VERSION 5.7 ;
  NOWIREEXTENSIONATPIN ON ;
  DIVIDERCHAR "/" ;
  BUSBITCHARS "[]" ;
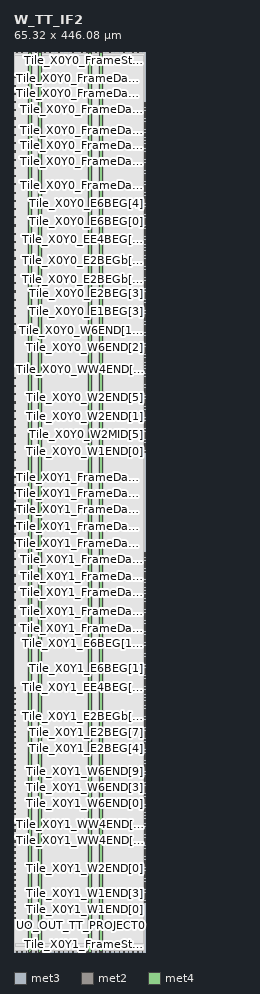
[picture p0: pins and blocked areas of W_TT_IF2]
MACRO W_TT_IF2
  CLASS BLOCK ;
  FOREIGN W_TT_IF2 ;
  ORIGIN 0.000 0.000 ;
  SIZE 65.320 BY 446.080 ;
  PIN CLK_TT_PROJECT
    DIRECTION OUTPUT ;
    USE SIGNAL ;
    ANTENNADIFFAREA 0.702900 ;
    PORT
      LAYER met3 ;
        RECT 0.000 127.880 0.600 128.480 ;
    END
  END CLK_TT_PROJECT
  PIN ENA_TT_PROJECT
    DIRECTION OUTPUT ;
    USE SIGNAL ;
    ANTENNADIFFAREA 0.702900 ;
    PORT
      LAYER met3 ;
        RECT 0.000 125.160 0.600 125.760 ;
    END
  END ENA_TT_PROJECT
  PIN RST_N_TT_PROJECT
    DIRECTION OUTPUT ;
    USE SIGNAL ;
    ANTENNADIFFAREA 0.702900 ;
    PORT
      LAYER met3 ;
        RECT 0.000 130.600 0.600 131.200 ;
    END
  END RST_N_TT_PROJECT
  PIN Tile_X0Y0_E1BEG[0]
    DIRECTION OUTPUT ;
    USE SIGNAL ;
    ANTENNADIFFAREA 0.702900 ;
    PORT
      LAYER met3 ;
        RECT 64.720 312.840 65.320 313.440 ;
    END
  END Tile_X0Y0_E1BEG[0]
  PIN Tile_X0Y0_E1BEG[1]
    DIRECTION OUTPUT ;
    USE SIGNAL ;
    ANTENNADIFFAREA 0.702900 ;
    PORT
      LAYER met3 ;
        RECT 64.720 314.200 65.320 314.800 ;
    END
  END Tile_X0Y0_E1BEG[1]
  PIN Tile_X0Y0_E1BEG[2]
    DIRECTION OUTPUT ;
    USE SIGNAL ;
    ANTENNADIFFAREA 0.702900 ;
    PORT
      LAYER met3 ;
        RECT 64.720 315.560 65.320 316.160 ;
    END
  END Tile_X0Y0_E1BEG[2]
  PIN Tile_X0Y0_E1BEG[3]
    DIRECTION OUTPUT ;
    USE SIGNAL ;
    ANTENNADIFFAREA 0.702900 ;
    PORT
      LAYER met3 ;
        RECT 64.720 316.920 65.320 317.520 ;
    END
  END Tile_X0Y0_E1BEG[3]
  PIN Tile_X0Y0_E2BEG[0]
    DIRECTION OUTPUT ;
    USE SIGNAL ;
    ANTENNADIFFAREA 0.702900 ;
    PORT
      LAYER met3 ;
        RECT 64.720 318.280 65.320 318.880 ;
    END
  END Tile_X0Y0_E2BEG[0]
  PIN Tile_X0Y0_E2BEG[1]
    DIRECTION OUTPUT ;
    USE SIGNAL ;
    ANTENNADIFFAREA 0.702900 ;
    PORT
      LAYER met3 ;
        RECT 64.720 319.640 65.320 320.240 ;
    END
  END Tile_X0Y0_E2BEG[1]
  PIN Tile_X0Y0_E2BEG[2]
    DIRECTION OUTPUT ;
    USE SIGNAL ;
    ANTENNADIFFAREA 0.702900 ;
    PORT
      LAYER met3 ;
        RECT 64.720 321.000 65.320 321.600 ;
    END
  END Tile_X0Y0_E2BEG[2]
  PIN Tile_X0Y0_E2BEG[3]
    DIRECTION OUTPUT ;
    USE SIGNAL ;
    ANTENNADIFFAREA 0.702900 ;
    PORT
      LAYER met3 ;
        RECT 64.720 322.360 65.320 322.960 ;
    END
  END Tile_X0Y0_E2BEG[3]
  PIN Tile_X0Y0_E2BEG[4]
    DIRECTION OUTPUT ;
    USE SIGNAL ;
    ANTENNADIFFAREA 0.702900 ;
    PORT
      LAYER met3 ;
        RECT 64.720 323.720 65.320 324.320 ;
    END
  END Tile_X0Y0_E2BEG[4]
  PIN Tile_X0Y0_E2BEG[5]
    DIRECTION OUTPUT ;
    USE SIGNAL ;
    ANTENNADIFFAREA 0.702900 ;
    PORT
      LAYER met3 ;
        RECT 64.720 325.080 65.320 325.680 ;
    END
  END Tile_X0Y0_E2BEG[5]
  PIN Tile_X0Y0_E2BEG[6]
    DIRECTION OUTPUT ;
    USE SIGNAL ;
    ANTENNADIFFAREA 0.702900 ;
    PORT
      LAYER met3 ;
        RECT 64.720 326.440 65.320 327.040 ;
    END
  END Tile_X0Y0_E2BEG[6]
  PIN Tile_X0Y0_E2BEG[7]
    DIRECTION OUTPUT ;
    USE SIGNAL ;
    ANTENNADIFFAREA 0.702900 ;
    PORT
      LAYER met3 ;
        RECT 64.720 327.800 65.320 328.400 ;
    END
  END Tile_X0Y0_E2BEG[7]
  PIN Tile_X0Y0_E2BEGb[0]
    DIRECTION OUTPUT ;
    USE SIGNAL ;
    ANTENNADIFFAREA 0.702900 ;
    PORT
      LAYER met3 ;
        RECT 64.720 329.160 65.320 329.760 ;
    END
  END Tile_X0Y0_E2BEGb[0]
  PIN Tile_X0Y0_E2BEGb[1]
    DIRECTION OUTPUT ;
    USE SIGNAL ;
    ANTENNADIFFAREA 0.702900 ;
    PORT
      LAYER met3 ;
        RECT 64.720 330.520 65.320 331.120 ;
    END
  END Tile_X0Y0_E2BEGb[1]
  PIN Tile_X0Y0_E2BEGb[2]
    DIRECTION OUTPUT ;
    USE SIGNAL ;
    ANTENNADIFFAREA 0.702900 ;
    PORT
      LAYER met3 ;
        RECT 64.720 331.880 65.320 332.480 ;
    END
  END Tile_X0Y0_E2BEGb[2]
  PIN Tile_X0Y0_E2BEGb[3]
    DIRECTION OUTPUT ;
    USE SIGNAL ;
    ANTENNADIFFAREA 0.702900 ;
    PORT
      LAYER met3 ;
        RECT 64.720 333.240 65.320 333.840 ;
    END
  END Tile_X0Y0_E2BEGb[3]
  PIN Tile_X0Y0_E2BEGb[4]
    DIRECTION OUTPUT ;
    USE SIGNAL ;
    ANTENNADIFFAREA 0.702900 ;
    PORT
      LAYER met3 ;
        RECT 64.720 334.600 65.320 335.200 ;
    END
  END Tile_X0Y0_E2BEGb[4]
  PIN Tile_X0Y0_E2BEGb[5]
    DIRECTION OUTPUT ;
    USE SIGNAL ;
    ANTENNADIFFAREA 0.702900 ;
    PORT
      LAYER met3 ;
        RECT 64.720 335.960 65.320 336.560 ;
    END
  END Tile_X0Y0_E2BEGb[5]
  PIN Tile_X0Y0_E2BEGb[6]
    DIRECTION OUTPUT ;
    USE SIGNAL ;
    ANTENNADIFFAREA 0.702900 ;
    PORT
      LAYER met3 ;
        RECT 64.720 337.320 65.320 337.920 ;
    END
  END Tile_X0Y0_E2BEGb[6]
  PIN Tile_X0Y0_E2BEGb[7]
    DIRECTION OUTPUT ;
    USE SIGNAL ;
    ANTENNADIFFAREA 0.702900 ;
    PORT
      LAYER met3 ;
        RECT 64.720 338.680 65.320 339.280 ;
    END
  END Tile_X0Y0_E2BEGb[7]
  PIN Tile_X0Y0_E6BEG[0]
    DIRECTION OUTPUT ;
    USE SIGNAL ;
    ANTENNADIFFAREA 0.702900 ;
    PORT
      LAYER met3 ;
        RECT 64.720 361.800 65.320 362.400 ;
    END
  END Tile_X0Y0_E6BEG[0]
  PIN Tile_X0Y0_E6BEG[10]
    DIRECTION OUTPUT ;
    USE SIGNAL ;
    ANTENNADIFFAREA 0.702900 ;
    PORT
      LAYER met3 ;
        RECT 64.720 375.400 65.320 376.000 ;
    END
  END Tile_X0Y0_E6BEG[10]
  PIN Tile_X0Y0_E6BEG[11]
    DIRECTION OUTPUT ;
    USE SIGNAL ;
    ANTENNADIFFAREA 0.702900 ;
    PORT
      LAYER met3 ;
        RECT 64.720 376.760 65.320 377.360 ;
    END
  END Tile_X0Y0_E6BEG[11]
  PIN Tile_X0Y0_E6BEG[1]
    DIRECTION OUTPUT ;
    USE SIGNAL ;
    ANTENNADIFFAREA 0.702900 ;
    PORT
      LAYER met3 ;
        RECT 64.720 363.160 65.320 363.760 ;
    END
  END Tile_X0Y0_E6BEG[1]
  PIN Tile_X0Y0_E6BEG[2]
    DIRECTION OUTPUT ;
    USE SIGNAL ;
    ANTENNADIFFAREA 0.702900 ;
    PORT
      LAYER met3 ;
        RECT 64.720 364.520 65.320 365.120 ;
    END
  END Tile_X0Y0_E6BEG[2]
  PIN Tile_X0Y0_E6BEG[3]
    DIRECTION OUTPUT ;
    USE SIGNAL ;
    ANTENNADIFFAREA 0.702900 ;
    PORT
      LAYER met3 ;
        RECT 64.720 365.880 65.320 366.480 ;
    END
  END Tile_X0Y0_E6BEG[3]
  PIN Tile_X0Y0_E6BEG[4]
    DIRECTION OUTPUT ;
    USE SIGNAL ;
    ANTENNADIFFAREA 0.702900 ;
    PORT
      LAYER met3 ;
        RECT 64.720 367.240 65.320 367.840 ;
    END
  END Tile_X0Y0_E6BEG[4]
  PIN Tile_X0Y0_E6BEG[5]
    DIRECTION OUTPUT ;
    USE SIGNAL ;
    ANTENNADIFFAREA 0.702900 ;
    PORT
      LAYER met3 ;
        RECT 64.720 368.600 65.320 369.200 ;
    END
  END Tile_X0Y0_E6BEG[5]
  PIN Tile_X0Y0_E6BEG[6]
    DIRECTION OUTPUT ;
    USE SIGNAL ;
    ANTENNADIFFAREA 0.702900 ;
    PORT
      LAYER met3 ;
        RECT 64.720 369.960 65.320 370.560 ;
    END
  END Tile_X0Y0_E6BEG[6]
  PIN Tile_X0Y0_E6BEG[7]
    DIRECTION OUTPUT ;
    USE SIGNAL ;
    ANTENNADIFFAREA 0.702900 ;
    PORT
      LAYER met3 ;
        RECT 64.720 371.320 65.320 371.920 ;
    END
  END Tile_X0Y0_E6BEG[7]
  PIN Tile_X0Y0_E6BEG[8]
    DIRECTION OUTPUT ;
    USE SIGNAL ;
    ANTENNADIFFAREA 0.702900 ;
    PORT
      LAYER met3 ;
        RECT 64.720 372.680 65.320 373.280 ;
    END
  END Tile_X0Y0_E6BEG[8]
  PIN Tile_X0Y0_E6BEG[9]
    DIRECTION OUTPUT ;
    USE SIGNAL ;
    ANTENNADIFFAREA 0.702900 ;
    PORT
      LAYER met3 ;
        RECT 64.720 374.040 65.320 374.640 ;
    END
  END Tile_X0Y0_E6BEG[9]
  PIN Tile_X0Y0_EE4BEG[0]
    DIRECTION OUTPUT ;
    USE SIGNAL ;
    ANTENNADIFFAREA 0.702900 ;
    PORT
      LAYER met3 ;
        RECT 64.720 340.040 65.320 340.640 ;
    END
  END Tile_X0Y0_EE4BEG[0]
  PIN Tile_X0Y0_EE4BEG[10]
    DIRECTION OUTPUT ;
    USE SIGNAL ;
    ANTENNADIFFAREA 0.702900 ;
    PORT
      LAYER met3 ;
        RECT 64.720 353.640 65.320 354.240 ;
    END
  END Tile_X0Y0_EE4BEG[10]
  PIN Tile_X0Y0_EE4BEG[11]
    DIRECTION OUTPUT ;
    USE SIGNAL ;
    ANTENNADIFFAREA 0.702900 ;
    PORT
      LAYER met3 ;
        RECT 64.720 355.000 65.320 355.600 ;
    END
  END Tile_X0Y0_EE4BEG[11]
  PIN Tile_X0Y0_EE4BEG[12]
    DIRECTION OUTPUT ;
    USE SIGNAL ;
    ANTENNADIFFAREA 0.702900 ;
    PORT
      LAYER met3 ;
        RECT 64.720 356.360 65.320 356.960 ;
    END
  END Tile_X0Y0_EE4BEG[12]
  PIN Tile_X0Y0_EE4BEG[13]
    DIRECTION OUTPUT ;
    USE SIGNAL ;
    ANTENNADIFFAREA 0.702900 ;
    PORT
      LAYER met3 ;
        RECT 64.720 357.720 65.320 358.320 ;
    END
  END Tile_X0Y0_EE4BEG[13]
  PIN Tile_X0Y0_EE4BEG[14]
    DIRECTION OUTPUT ;
    USE SIGNAL ;
    ANTENNADIFFAREA 0.702900 ;
    PORT
      LAYER met3 ;
        RECT 64.720 359.080 65.320 359.680 ;
    END
  END Tile_X0Y0_EE4BEG[14]
  PIN Tile_X0Y0_EE4BEG[15]
    DIRECTION OUTPUT ;
    USE SIGNAL ;
    ANTENNADIFFAREA 0.702900 ;
    PORT
      LAYER met3 ;
        RECT 64.720 360.440 65.320 361.040 ;
    END
  END Tile_X0Y0_EE4BEG[15]
  PIN Tile_X0Y0_EE4BEG[1]
    DIRECTION OUTPUT ;
    USE SIGNAL ;
    ANTENNADIFFAREA 0.702900 ;
    PORT
      LAYER met3 ;
        RECT 64.720 341.400 65.320 342.000 ;
    END
  END Tile_X0Y0_EE4BEG[1]
  PIN Tile_X0Y0_EE4BEG[2]
    DIRECTION OUTPUT ;
    USE SIGNAL ;
    ANTENNADIFFAREA 0.702900 ;
    PORT
      LAYER met3 ;
        RECT 64.720 342.760 65.320 343.360 ;
    END
  END Tile_X0Y0_EE4BEG[2]
  PIN Tile_X0Y0_EE4BEG[3]
    DIRECTION OUTPUT ;
    USE SIGNAL ;
    ANTENNADIFFAREA 0.702900 ;
    PORT
      LAYER met3 ;
        RECT 64.720 344.120 65.320 344.720 ;
    END
  END Tile_X0Y0_EE4BEG[3]
  PIN Tile_X0Y0_EE4BEG[4]
    DIRECTION OUTPUT ;
    USE SIGNAL ;
    ANTENNADIFFAREA 0.702900 ;
    PORT
      LAYER met3 ;
        RECT 64.720 345.480 65.320 346.080 ;
    END
  END Tile_X0Y0_EE4BEG[4]
  PIN Tile_X0Y0_EE4BEG[5]
    DIRECTION OUTPUT ;
    USE SIGNAL ;
    ANTENNADIFFAREA 0.702900 ;
    PORT
      LAYER met3 ;
        RECT 64.720 346.840 65.320 347.440 ;
    END
  END Tile_X0Y0_EE4BEG[5]
  PIN Tile_X0Y0_EE4BEG[6]
    DIRECTION OUTPUT ;
    USE SIGNAL ;
    ANTENNADIFFAREA 0.702900 ;
    PORT
      LAYER met3 ;
        RECT 64.720 348.200 65.320 348.800 ;
    END
  END Tile_X0Y0_EE4BEG[6]
  PIN Tile_X0Y0_EE4BEG[7]
    DIRECTION OUTPUT ;
    USE SIGNAL ;
    ANTENNADIFFAREA 0.702900 ;
    PORT
      LAYER met3 ;
        RECT 64.720 349.560 65.320 350.160 ;
    END
  END Tile_X0Y0_EE4BEG[7]
  PIN Tile_X0Y0_EE4BEG[8]
    DIRECTION OUTPUT ;
    USE SIGNAL ;
    ANTENNADIFFAREA 0.702900 ;
    PORT
      LAYER met3 ;
        RECT 64.720 350.920 65.320 351.520 ;
    END
  END Tile_X0Y0_EE4BEG[8]
  PIN Tile_X0Y0_EE4BEG[9]
    DIRECTION OUTPUT ;
    USE SIGNAL ;
    ANTENNADIFFAREA 0.702900 ;
    PORT
      LAYER met3 ;
        RECT 64.720 352.280 65.320 352.880 ;
    END
  END Tile_X0Y0_EE4BEG[9]
  PIN Tile_X0Y0_FrameData[0]
    DIRECTION INPUT ;
    USE SIGNAL ;
    ANTENNAGATEAREA 1.505400 ;
    ANTENNADIFFAREA 0.869400 ;
    PORT
      LAYER met3 ;
        RECT 0.000 306.720 0.600 307.320 ;
    END
  END Tile_X0Y0_FrameData[0]
  PIN Tile_X0Y0_FrameData[10]
    DIRECTION INPUT ;
    USE SIGNAL ;
    ANTENNAGATEAREA 0.795000 ;
    PORT
      LAYER met3 ;
        RECT 0.000 347.520 0.600 348.120 ;
    END
  END Tile_X0Y0_FrameData[10]
  PIN Tile_X0Y0_FrameData[11]
    DIRECTION INPUT ;
    USE SIGNAL ;
    ANTENNAGATEAREA 0.795000 ;
    PORT
      LAYER met3 ;
        RECT 0.000 351.600 0.600 352.200 ;
    END
  END Tile_X0Y0_FrameData[11]
  PIN Tile_X0Y0_FrameData[12]
    DIRECTION INPUT ;
    USE SIGNAL ;
    ANTENNAGATEAREA 0.795000 ;
    PORT
      LAYER met3 ;
        RECT 0.000 355.680 0.600 356.280 ;
    END
  END Tile_X0Y0_FrameData[12]
  PIN Tile_X0Y0_FrameData[13]
    DIRECTION INPUT ;
    USE SIGNAL ;
    ANTENNAGATEAREA 0.795000 ;
    PORT
      LAYER met3 ;
        RECT 0.000 359.760 0.600 360.360 ;
    END
  END Tile_X0Y0_FrameData[13]
  PIN Tile_X0Y0_FrameData[14]
    DIRECTION INPUT ;
    USE SIGNAL ;
    ANTENNAGATEAREA 0.795000 ;
    PORT
      LAYER met3 ;
        RECT 0.000 363.840 0.600 364.440 ;
    END
  END Tile_X0Y0_FrameData[14]
  PIN Tile_X0Y0_FrameData[15]
    DIRECTION INPUT ;
    USE SIGNAL ;
    ANTENNAGATEAREA 0.795000 ;
    PORT
      LAYER met3 ;
        RECT 0.000 367.920 0.600 368.520 ;
    END
  END Tile_X0Y0_FrameData[15]
  PIN Tile_X0Y0_FrameData[16]
    DIRECTION INPUT ;
    USE SIGNAL ;
    ANTENNAGATEAREA 0.795000 ;
    PORT
      LAYER met3 ;
        RECT 0.000 372.000 0.600 372.600 ;
    END
  END Tile_X0Y0_FrameData[16]
  PIN Tile_X0Y0_FrameData[17]
    DIRECTION INPUT ;
    USE SIGNAL ;
    ANTENNAGATEAREA 0.795000 ;
    PORT
      LAYER met3 ;
        RECT 0.000 376.080 0.600 376.680 ;
    END
  END Tile_X0Y0_FrameData[17]
  PIN Tile_X0Y0_FrameData[18]
    DIRECTION INPUT ;
    USE SIGNAL ;
    ANTENNAGATEAREA 0.795000 ;
    PORT
      LAYER met3 ;
        RECT 0.000 380.160 0.600 380.760 ;
    END
  END Tile_X0Y0_FrameData[18]
  PIN Tile_X0Y0_FrameData[19]
    DIRECTION INPUT ;
    USE SIGNAL ;
    ANTENNAGATEAREA 0.795000 ;
    PORT
      LAYER met3 ;
        RECT 0.000 384.240 0.600 384.840 ;
    END
  END Tile_X0Y0_FrameData[19]
  PIN Tile_X0Y0_FrameData[1]
    DIRECTION INPUT ;
    USE SIGNAL ;
    ANTENNAGATEAREA 1.070700 ;
    ANTENNADIFFAREA 0.434700 ;
    PORT
      LAYER met3 ;
        RECT 0.000 310.800 0.600 311.400 ;
    END
  END Tile_X0Y0_FrameData[1]
  PIN Tile_X0Y0_FrameData[20]
    DIRECTION INPUT ;
    USE SIGNAL ;
    ANTENNAGATEAREA 0.795000 ;
    PORT
      LAYER met3 ;
        RECT 0.000 388.320 0.600 388.920 ;
    END
  END Tile_X0Y0_FrameData[20]
  PIN Tile_X0Y0_FrameData[21]
    DIRECTION INPUT ;
    USE SIGNAL ;
    ANTENNAGATEAREA 0.795000 ;
    PORT
      LAYER met3 ;
        RECT 0.000 392.400 0.600 393.000 ;
    END
  END Tile_X0Y0_FrameData[21]
  PIN Tile_X0Y0_FrameData[22]
    DIRECTION INPUT ;
    USE SIGNAL ;
    ANTENNAGATEAREA 0.795000 ;
    PORT
      LAYER met3 ;
        RECT 0.000 396.480 0.600 397.080 ;
    END
  END Tile_X0Y0_FrameData[22]
  PIN Tile_X0Y0_FrameData[23]
    DIRECTION INPUT ;
    USE SIGNAL ;
    ANTENNAGATEAREA 0.795000 ;
    PORT
      LAYER met3 ;
        RECT 0.000 400.560 0.600 401.160 ;
    END
  END Tile_X0Y0_FrameData[23]
  PIN Tile_X0Y0_FrameData[24]
    DIRECTION INPUT ;
    USE SIGNAL ;
    ANTENNAGATEAREA 0.795000 ;
    PORT
      LAYER met3 ;
        RECT 0.000 404.640 0.600 405.240 ;
    END
  END Tile_X0Y0_FrameData[24]
  PIN Tile_X0Y0_FrameData[25]
    DIRECTION INPUT ;
    USE SIGNAL ;
    ANTENNAGATEAREA 1.229700 ;
    ANTENNADIFFAREA 0.434700 ;
    PORT
      LAYER met3 ;
        RECT 0.000 408.720 0.600 409.320 ;
    END
  END Tile_X0Y0_FrameData[25]
  PIN Tile_X0Y0_FrameData[26]
    DIRECTION INPUT ;
    USE SIGNAL ;
    ANTENNAGATEAREA 1.229700 ;
    ANTENNADIFFAREA 0.434700 ;
    PORT
      LAYER met3 ;
        RECT 0.000 412.800 0.600 413.400 ;
    END
  END Tile_X0Y0_FrameData[26]
  PIN Tile_X0Y0_FrameData[27]
    DIRECTION INPUT ;
    USE SIGNAL ;
    ANTENNAGATEAREA 0.795000 ;
    PORT
      LAYER met3 ;
        RECT 0.000 416.880 0.600 417.480 ;
    END
  END Tile_X0Y0_FrameData[27]
  PIN Tile_X0Y0_FrameData[28]
    DIRECTION INPUT ;
    USE SIGNAL ;
    ANTENNAGATEAREA 1.229700 ;
    ANTENNADIFFAREA 0.434700 ;
    PORT
      LAYER met3 ;
        RECT 0.000 420.960 0.600 421.560 ;
    END
  END Tile_X0Y0_FrameData[28]
  PIN Tile_X0Y0_FrameData[29]
    DIRECTION INPUT ;
    USE SIGNAL ;
    ANTENNAGATEAREA 1.229700 ;
    ANTENNADIFFAREA 0.434700 ;
    PORT
      LAYER met3 ;
        RECT 0.000 425.040 0.600 425.640 ;
    END
  END Tile_X0Y0_FrameData[29]
  PIN Tile_X0Y0_FrameData[2]
    DIRECTION INPUT ;
    USE SIGNAL ;
    ANTENNAGATEAREA 0.636000 ;
    PORT
      LAYER met3 ;
        RECT 0.000 314.880 0.600 315.480 ;
    END
  END Tile_X0Y0_FrameData[2]
  PIN Tile_X0Y0_FrameData[30]
    DIRECTION INPUT ;
    USE SIGNAL ;
    ANTENNAGATEAREA 0.795000 ;
    PORT
      LAYER met3 ;
        RECT 0.000 429.120 0.600 429.720 ;
    END
  END Tile_X0Y0_FrameData[30]
  PIN Tile_X0Y0_FrameData[31]
    DIRECTION INPUT ;
    USE SIGNAL ;
    ANTENNAGATEAREA 0.795000 ;
    PORT
      LAYER met3 ;
        RECT 0.000 433.200 0.600 433.800 ;
    END
  END Tile_X0Y0_FrameData[31]
  PIN Tile_X0Y0_FrameData[3]
    DIRECTION INPUT ;
    USE SIGNAL ;
    ANTENNAGATEAREA 0.636000 ;
    PORT
      LAYER met3 ;
        RECT 0.000 318.960 0.600 319.560 ;
    END
  END Tile_X0Y0_FrameData[3]
  PIN Tile_X0Y0_FrameData[4]
    DIRECTION INPUT ;
    USE SIGNAL ;
    ANTENNAGATEAREA 0.795000 ;
    PORT
      LAYER met3 ;
        RECT 0.000 323.040 0.600 323.640 ;
    END
  END Tile_X0Y0_FrameData[4]
  PIN Tile_X0Y0_FrameData[5]
    DIRECTION INPUT ;
    USE SIGNAL ;
    ANTENNAGATEAREA 0.795000 ;
    PORT
      LAYER met3 ;
        RECT 0.000 327.120 0.600 327.720 ;
    END
  END Tile_X0Y0_FrameData[5]
  PIN Tile_X0Y0_FrameData[6]
    DIRECTION INPUT ;
    USE SIGNAL ;
    ANTENNAGATEAREA 0.795000 ;
    PORT
      LAYER met3 ;
        RECT 0.000 331.200 0.600 331.800 ;
    END
  END Tile_X0Y0_FrameData[6]
  PIN Tile_X0Y0_FrameData[7]
    DIRECTION INPUT ;
    USE SIGNAL ;
    ANTENNAGATEAREA 0.795000 ;
    PORT
      LAYER met3 ;
        RECT 0.000 335.280 0.600 335.880 ;
    END
  END Tile_X0Y0_FrameData[7]
  PIN Tile_X0Y0_FrameData[8]
    DIRECTION INPUT ;
    USE SIGNAL ;
    ANTENNAGATEAREA 0.795000 ;
    PORT
      LAYER met3 ;
        RECT 0.000 339.360 0.600 339.960 ;
    END
  END Tile_X0Y0_FrameData[8]
  PIN Tile_X0Y0_FrameData[9]
    DIRECTION INPUT ;
    USE SIGNAL ;
    ANTENNAGATEAREA 1.229700 ;
    ANTENNADIFFAREA 0.434700 ;
    PORT
      LAYER met3 ;
        RECT 0.000 343.440 0.600 344.040 ;
    END
  END Tile_X0Y0_FrameData[9]
  PIN Tile_X0Y0_FrameData_O[0]
    DIRECTION OUTPUT ;
    USE SIGNAL ;
    ANTENNADIFFAREA 0.702900 ;
    PORT
      LAYER met3 ;
        RECT 64.720 378.120 65.320 378.720 ;
    END
  END Tile_X0Y0_FrameData_O[0]
  PIN Tile_X0Y0_FrameData_O[10]
    DIRECTION OUTPUT ;
    USE SIGNAL ;
    ANTENNADIFFAREA 0.702900 ;
    PORT
      LAYER met3 ;
        RECT 64.720 391.720 65.320 392.320 ;
    END
  END Tile_X0Y0_FrameData_O[10]
  PIN Tile_X0Y0_FrameData_O[11]
    DIRECTION OUTPUT ;
    USE SIGNAL ;
    ANTENNADIFFAREA 0.702900 ;
    PORT
      LAYER met3 ;
        RECT 64.720 393.080 65.320 393.680 ;
    END
  END Tile_X0Y0_FrameData_O[11]
  PIN Tile_X0Y0_FrameData_O[12]
    DIRECTION OUTPUT ;
    USE SIGNAL ;
    ANTENNADIFFAREA 0.702900 ;
    PORT
      LAYER met3 ;
        RECT 64.720 394.440 65.320 395.040 ;
    END
  END Tile_X0Y0_FrameData_O[12]
  PIN Tile_X0Y0_FrameData_O[13]
    DIRECTION OUTPUT ;
    USE SIGNAL ;
    ANTENNADIFFAREA 0.702900 ;
    PORT
      LAYER met3 ;
        RECT 64.720 395.800 65.320 396.400 ;
    END
  END Tile_X0Y0_FrameData_O[13]
  PIN Tile_X0Y0_FrameData_O[14]
    DIRECTION OUTPUT ;
    USE SIGNAL ;
    ANTENNADIFFAREA 0.702900 ;
    PORT
      LAYER met3 ;
        RECT 64.720 397.160 65.320 397.760 ;
    END
  END Tile_X0Y0_FrameData_O[14]
  PIN Tile_X0Y0_FrameData_O[15]
    DIRECTION OUTPUT ;
    USE SIGNAL ;
    ANTENNADIFFAREA 0.702900 ;
    PORT
      LAYER met3 ;
        RECT 64.720 398.520 65.320 399.120 ;
    END
  END Tile_X0Y0_FrameData_O[15]
  PIN Tile_X0Y0_FrameData_O[16]
    DIRECTION OUTPUT ;
    USE SIGNAL ;
    ANTENNADIFFAREA 0.702900 ;
    PORT
      LAYER met3 ;
        RECT 64.720 399.880 65.320 400.480 ;
    END
  END Tile_X0Y0_FrameData_O[16]
  PIN Tile_X0Y0_FrameData_O[17]
    DIRECTION OUTPUT ;
    USE SIGNAL ;
    ANTENNADIFFAREA 0.702900 ;
    PORT
      LAYER met3 ;
        RECT 64.720 401.240 65.320 401.840 ;
    END
  END Tile_X0Y0_FrameData_O[17]
  PIN Tile_X0Y0_FrameData_O[18]
    DIRECTION OUTPUT ;
    USE SIGNAL ;
    ANTENNADIFFAREA 0.702900 ;
    PORT
      LAYER met3 ;
        RECT 64.720 402.600 65.320 403.200 ;
    END
  END Tile_X0Y0_FrameData_O[18]
  PIN Tile_X0Y0_FrameData_O[19]
    DIRECTION OUTPUT ;
    USE SIGNAL ;
    ANTENNADIFFAREA 0.702900 ;
    PORT
      LAYER met3 ;
        RECT 64.720 403.960 65.320 404.560 ;
    END
  END Tile_X0Y0_FrameData_O[19]
  PIN Tile_X0Y0_FrameData_O[1]
    DIRECTION OUTPUT ;
    USE SIGNAL ;
    ANTENNADIFFAREA 0.702900 ;
    PORT
      LAYER met3 ;
        RECT 64.720 379.480 65.320 380.080 ;
    END
  END Tile_X0Y0_FrameData_O[1]
  PIN Tile_X0Y0_FrameData_O[20]
    DIRECTION OUTPUT ;
    USE SIGNAL ;
    ANTENNADIFFAREA 0.702900 ;
    PORT
      LAYER met3 ;
        RECT 64.720 405.320 65.320 405.920 ;
    END
  END Tile_X0Y0_FrameData_O[20]
  PIN Tile_X0Y0_FrameData_O[21]
    DIRECTION OUTPUT ;
    USE SIGNAL ;
    ANTENNADIFFAREA 0.702900 ;
    PORT
      LAYER met3 ;
        RECT 64.720 406.680 65.320 407.280 ;
    END
  END Tile_X0Y0_FrameData_O[21]
  PIN Tile_X0Y0_FrameData_O[22]
    DIRECTION OUTPUT ;
    USE SIGNAL ;
    ANTENNADIFFAREA 0.702900 ;
    PORT
      LAYER met3 ;
        RECT 64.720 408.040 65.320 408.640 ;
    END
  END Tile_X0Y0_FrameData_O[22]
  PIN Tile_X0Y0_FrameData_O[23]
    DIRECTION OUTPUT ;
    USE SIGNAL ;
    ANTENNADIFFAREA 0.702900 ;
    PORT
      LAYER met3 ;
        RECT 64.720 409.400 65.320 410.000 ;
    END
  END Tile_X0Y0_FrameData_O[23]
  PIN Tile_X0Y0_FrameData_O[24]
    DIRECTION OUTPUT ;
    USE SIGNAL ;
    ANTENNADIFFAREA 0.702900 ;
    PORT
      LAYER met3 ;
        RECT 64.720 410.760 65.320 411.360 ;
    END
  END Tile_X0Y0_FrameData_O[24]
  PIN Tile_X0Y0_FrameData_O[25]
    DIRECTION OUTPUT ;
    USE SIGNAL ;
    ANTENNADIFFAREA 0.702900 ;
    PORT
      LAYER met3 ;
        RECT 64.720 412.120 65.320 412.720 ;
    END
  END Tile_X0Y0_FrameData_O[25]
  PIN Tile_X0Y0_FrameData_O[26]
    DIRECTION OUTPUT ;
    USE SIGNAL ;
    ANTENNADIFFAREA 0.702900 ;
    PORT
      LAYER met3 ;
        RECT 64.720 413.480 65.320 414.080 ;
    END
  END Tile_X0Y0_FrameData_O[26]
  PIN Tile_X0Y0_FrameData_O[27]
    DIRECTION OUTPUT ;
    USE SIGNAL ;
    ANTENNADIFFAREA 0.702900 ;
    PORT
      LAYER met3 ;
        RECT 64.720 414.840 65.320 415.440 ;
    END
  END Tile_X0Y0_FrameData_O[27]
  PIN Tile_X0Y0_FrameData_O[28]
    DIRECTION OUTPUT ;
    USE SIGNAL ;
    ANTENNADIFFAREA 0.702900 ;
    PORT
      LAYER met3 ;
        RECT 64.720 416.200 65.320 416.800 ;
    END
  END Tile_X0Y0_FrameData_O[28]
  PIN Tile_X0Y0_FrameData_O[29]
    DIRECTION OUTPUT ;
    USE SIGNAL ;
    ANTENNADIFFAREA 0.702900 ;
    PORT
      LAYER met3 ;
        RECT 64.720 417.560 65.320 418.160 ;
    END
  END Tile_X0Y0_FrameData_O[29]
  PIN Tile_X0Y0_FrameData_O[2]
    DIRECTION OUTPUT ;
    USE SIGNAL ;
    ANTENNADIFFAREA 0.702900 ;
    PORT
      LAYER met3 ;
        RECT 64.720 380.840 65.320 381.440 ;
    END
  END Tile_X0Y0_FrameData_O[2]
  PIN Tile_X0Y0_FrameData_O[30]
    DIRECTION OUTPUT ;
    USE SIGNAL ;
    ANTENNADIFFAREA 0.702900 ;
    PORT
      LAYER met3 ;
        RECT 64.720 418.920 65.320 419.520 ;
    END
  END Tile_X0Y0_FrameData_O[30]
  PIN Tile_X0Y0_FrameData_O[31]
    DIRECTION OUTPUT ;
    USE SIGNAL ;
    ANTENNADIFFAREA 0.702900 ;
    PORT
      LAYER met3 ;
        RECT 64.720 420.280 65.320 420.880 ;
    END
  END Tile_X0Y0_FrameData_O[31]
  PIN Tile_X0Y0_FrameData_O[3]
    DIRECTION OUTPUT ;
    USE SIGNAL ;
    ANTENNADIFFAREA 0.702900 ;
    PORT
      LAYER met3 ;
        RECT 64.720 382.200 65.320 382.800 ;
    END
  END Tile_X0Y0_FrameData_O[3]
  PIN Tile_X0Y0_FrameData_O[4]
    DIRECTION OUTPUT ;
    USE SIGNAL ;
    ANTENNADIFFAREA 0.702900 ;
    PORT
      LAYER met3 ;
        RECT 64.720 383.560 65.320 384.160 ;
    END
  END Tile_X0Y0_FrameData_O[4]
  PIN Tile_X0Y0_FrameData_O[5]
    DIRECTION OUTPUT ;
    USE SIGNAL ;
    ANTENNADIFFAREA 0.702900 ;
    PORT
      LAYER met3 ;
        RECT 64.720 384.920 65.320 385.520 ;
    END
  END Tile_X0Y0_FrameData_O[5]
  PIN Tile_X0Y0_FrameData_O[6]
    DIRECTION OUTPUT ;
    USE SIGNAL ;
    ANTENNADIFFAREA 0.702900 ;
    PORT
      LAYER met3 ;
        RECT 64.720 386.280 65.320 386.880 ;
    END
  END Tile_X0Y0_FrameData_O[6]
  PIN Tile_X0Y0_FrameData_O[7]
    DIRECTION OUTPUT ;
    USE SIGNAL ;
    ANTENNADIFFAREA 0.702900 ;
    PORT
      LAYER met3 ;
        RECT 64.720 387.640 65.320 388.240 ;
    END
  END Tile_X0Y0_FrameData_O[7]
  PIN Tile_X0Y0_FrameData_O[8]
    DIRECTION OUTPUT ;
    USE SIGNAL ;
    ANTENNADIFFAREA 0.702900 ;
    PORT
      LAYER met3 ;
        RECT 64.720 389.000 65.320 389.600 ;
    END
  END Tile_X0Y0_FrameData_O[8]
  PIN Tile_X0Y0_FrameData_O[9]
    DIRECTION OUTPUT ;
    USE SIGNAL ;
    ANTENNADIFFAREA 0.702900 ;
    PORT
      LAYER met3 ;
        RECT 64.720 390.360 65.320 390.960 ;
    END
  END Tile_X0Y0_FrameData_O[9]
  PIN Tile_X0Y0_FrameStrobe_O[0]
    DIRECTION OUTPUT ;
    USE SIGNAL ;
    ANTENNADIFFAREA 0.702900 ;
    PORT
      LAYER met2 ;
        RECT 19.870 445.800 20.150 446.080 ;
    END
  END Tile_X0Y0_FrameStrobe_O[0]
  PIN Tile_X0Y0_FrameStrobe_O[10]
    DIRECTION OUTPUT ;
    USE SIGNAL ;
    ANTENNADIFFAREA 0.702900 ;
    PORT
      LAYER met2 ;
        RECT 42.870 445.800 43.150 446.080 ;
    END
  END Tile_X0Y0_FrameStrobe_O[10]
  PIN Tile_X0Y0_FrameStrobe_O[11]
    DIRECTION OUTPUT ;
    USE SIGNAL ;
    ANTENNADIFFAREA 0.702900 ;
    PORT
      LAYER met2 ;
        RECT 45.170 445.800 45.450 446.080 ;
    END
  END Tile_X0Y0_FrameStrobe_O[11]
  PIN Tile_X0Y0_FrameStrobe_O[12]
    DIRECTION OUTPUT ;
    USE SIGNAL ;
    ANTENNADIFFAREA 0.702900 ;
    PORT
      LAYER met2 ;
        RECT 47.470 445.800 47.750 446.080 ;
    END
  END Tile_X0Y0_FrameStrobe_O[12]
  PIN Tile_X0Y0_FrameStrobe_O[13]
    DIRECTION OUTPUT ;
    USE SIGNAL ;
    ANTENNADIFFAREA 0.702900 ;
    PORT
      LAYER met2 ;
        RECT 49.770 445.800 50.050 446.080 ;
    END
  END Tile_X0Y0_FrameStrobe_O[13]
  PIN Tile_X0Y0_FrameStrobe_O[14]
    DIRECTION OUTPUT ;
    USE SIGNAL ;
    ANTENNADIFFAREA 0.702900 ;
    PORT
      LAYER met2 ;
        RECT 52.070 445.800 52.350 446.080 ;
    END
  END Tile_X0Y0_FrameStrobe_O[14]
  PIN Tile_X0Y0_FrameStrobe_O[15]
    DIRECTION OUTPUT ;
    USE SIGNAL ;
    ANTENNADIFFAREA 0.702900 ;
    PORT
      LAYER met2 ;
        RECT 54.370 445.800 54.650 446.080 ;
    END
  END Tile_X0Y0_FrameStrobe_O[15]
  PIN Tile_X0Y0_FrameStrobe_O[16]
    DIRECTION OUTPUT ;
    USE SIGNAL ;
    ANTENNADIFFAREA 0.702900 ;
    PORT
      LAYER met2 ;
        RECT 56.670 445.800 56.950 446.080 ;
    END
  END Tile_X0Y0_FrameStrobe_O[16]
  PIN Tile_X0Y0_FrameStrobe_O[17]
    DIRECTION OUTPUT ;
    USE SIGNAL ;
    ANTENNADIFFAREA 0.702900 ;
    PORT
      LAYER met2 ;
        RECT 58.970 445.800 59.250 446.080 ;
    END
  END Tile_X0Y0_FrameStrobe_O[17]
  PIN Tile_X0Y0_FrameStrobe_O[18]
    DIRECTION OUTPUT ;
    USE SIGNAL ;
    ANTENNADIFFAREA 0.702900 ;
    PORT
      LAYER met2 ;
        RECT 61.270 445.800 61.550 446.080 ;
    END
  END Tile_X0Y0_FrameStrobe_O[18]
  PIN Tile_X0Y0_FrameStrobe_O[19]
    DIRECTION OUTPUT ;
    USE SIGNAL ;
    ANTENNADIFFAREA 0.702900 ;
    PORT
      LAYER met2 ;
        RECT 63.570 445.800 63.850 446.080 ;
    END
  END Tile_X0Y0_FrameStrobe_O[19]
  PIN Tile_X0Y0_FrameStrobe_O[1]
    DIRECTION OUTPUT ;
    USE SIGNAL ;
    ANTENNADIFFAREA 0.702900 ;
    PORT
      LAYER met2 ;
        RECT 22.170 445.800 22.450 446.080 ;
    END
  END Tile_X0Y0_FrameStrobe_O[1]
  PIN Tile_X0Y0_FrameStrobe_O[2]
    DIRECTION OUTPUT ;
    USE SIGNAL ;
    ANTENNADIFFAREA 0.702900 ;
    PORT
      LAYER met2 ;
        RECT 24.470 445.800 24.750 446.080 ;
    END
  END Tile_X0Y0_FrameStrobe_O[2]
  PIN Tile_X0Y0_FrameStrobe_O[3]
    DIRECTION OUTPUT ;
    USE SIGNAL ;
    ANTENNADIFFAREA 0.702900 ;
    PORT
      LAYER met2 ;
        RECT 26.770 445.800 27.050 446.080 ;
    END
  END Tile_X0Y0_FrameStrobe_O[3]
  PIN Tile_X0Y0_FrameStrobe_O[4]
    DIRECTION OUTPUT ;
    USE SIGNAL ;
    ANTENNADIFFAREA 0.702900 ;
    PORT
      LAYER met2 ;
        RECT 29.070 445.800 29.350 446.080 ;
    END
  END Tile_X0Y0_FrameStrobe_O[4]
  PIN Tile_X0Y0_FrameStrobe_O[5]
    DIRECTION OUTPUT ;
    USE SIGNAL ;
    ANTENNADIFFAREA 0.702900 ;
    PORT
      LAYER met2 ;
        RECT 31.370 445.800 31.650 446.080 ;
    END
  END Tile_X0Y0_FrameStrobe_O[5]
  PIN Tile_X0Y0_FrameStrobe_O[6]
    DIRECTION OUTPUT ;
    USE SIGNAL ;
    ANTENNADIFFAREA 0.702900 ;
    PORT
      LAYER met2 ;
        RECT 33.670 445.800 33.950 446.080 ;
    END
  END Tile_X0Y0_FrameStrobe_O[6]
  PIN Tile_X0Y0_FrameStrobe_O[7]
    DIRECTION OUTPUT ;
    USE SIGNAL ;
    ANTENNADIFFAREA 0.702900 ;
    PORT
      LAYER met2 ;
        RECT 35.970 445.800 36.250 446.080 ;
    END
  END Tile_X0Y0_FrameStrobe_O[7]
  PIN Tile_X0Y0_FrameStrobe_O[8]
    DIRECTION OUTPUT ;
    USE SIGNAL ;
    ANTENNADIFFAREA 0.702900 ;
    PORT
      LAYER met2 ;
        RECT 38.270 445.800 38.550 446.080 ;
    END
  END Tile_X0Y0_FrameStrobe_O[8]
  PIN Tile_X0Y0_FrameStrobe_O[9]
    DIRECTION OUTPUT ;
    USE SIGNAL ;
    ANTENNADIFFAREA 0.702900 ;
    PORT
      LAYER met2 ;
        RECT 40.570 445.800 40.850 446.080 ;
    END
  END Tile_X0Y0_FrameStrobe_O[9]
  PIN Tile_X0Y0_N_GBUF_BEG[0]
    DIRECTION OUTPUT ;
    USE SIGNAL ;
    ANTENNADIFFAREA 0.702900 ;
    PORT
      LAYER met2 ;
        RECT 1.470 445.800 1.750 446.080 ;
    END
  END Tile_X0Y0_N_GBUF_BEG[0]
  PIN Tile_X0Y0_N_GBUF_BEG[1]
    DIRECTION OUTPUT ;
    USE SIGNAL ;
    ANTENNADIFFAREA 0.702900 ;
    PORT
      LAYER met2 ;
        RECT 3.770 445.800 4.050 446.080 ;
    END
  END Tile_X0Y0_N_GBUF_BEG[1]
  PIN Tile_X0Y0_N_GBUF_BEG[2]
    DIRECTION OUTPUT ;
    USE SIGNAL ;
    ANTENNADIFFAREA 0.702900 ;
    PORT
      LAYER met2 ;
        RECT 6.070 445.800 6.350 446.080 ;
    END
  END Tile_X0Y0_N_GBUF_BEG[2]
  PIN Tile_X0Y0_N_GBUF_BEG[3]
    DIRECTION OUTPUT ;
    USE SIGNAL ;
    ANTENNADIFFAREA 0.702900 ;
    PORT
      LAYER met2 ;
        RECT 8.370 445.800 8.650 446.080 ;
    END
  END Tile_X0Y0_N_GBUF_BEG[3]
  PIN Tile_X0Y0_S_GBUF_FEED_END[0]
    DIRECTION INPUT ;
    USE SIGNAL ;
    ANTENNAGATEAREA 0.593700 ;
    ANTENNADIFFAREA 0.434700 ;
    PORT
      LAYER met2 ;
        RECT 10.670 445.800 10.950 446.080 ;
    END
  END Tile_X0Y0_S_GBUF_FEED_END[0]
  PIN Tile_X0Y0_S_GBUF_FEED_END[1]
    DIRECTION INPUT ;
    USE SIGNAL ;
    ANTENNAGATEAREA 0.593700 ;
    ANTENNADIFFAREA 0.434700 ;
    PORT
      LAYER met2 ;
        RECT 12.970 445.800 13.250 446.080 ;
    END
  END Tile_X0Y0_S_GBUF_FEED_END[1]
  PIN Tile_X0Y0_S_GBUF_FEED_END[2]
    DIRECTION INPUT ;
    USE SIGNAL ;
    ANTENNAGATEAREA 0.593700 ;
    ANTENNADIFFAREA 0.434700 ;
    PORT
      LAYER met2 ;
        RECT 15.270 445.800 15.550 446.080 ;
    END
  END Tile_X0Y0_S_GBUF_FEED_END[2]
  PIN Tile_X0Y0_S_GBUF_FEED_END[3]
    DIRECTION INPUT ;
    USE SIGNAL ;
    ANTENNAGATEAREA 0.593700 ;
    ANTENNADIFFAREA 0.434700 ;
    PORT
      LAYER met2 ;
        RECT 17.570 445.800 17.850 446.080 ;
    END
  END Tile_X0Y0_S_GBUF_FEED_END[3]
  PIN Tile_X0Y0_W1END[0]
    DIRECTION INPUT ;
    USE SIGNAL ;
    ANTENNAGATEAREA 1.004700 ;
    ANTENNADIFFAREA 0.434700 ;
    PORT
      LAYER met3 ;
        RECT 64.720 247.560 65.320 248.160 ;
    END
  END Tile_X0Y0_W1END[0]
  PIN Tile_X0Y0_W1END[1]
    DIRECTION INPUT ;
    USE SIGNAL ;
    ANTENNAGATEAREA 0.570000 ;
    PORT
      LAYER met3 ;
        RECT 64.720 248.920 65.320 249.520 ;
    END
  END Tile_X0Y0_W1END[1]
  PIN Tile_X0Y0_W1END[2]
    DIRECTION INPUT ;
    USE SIGNAL ;
    ANTENNAGATEAREA 0.570000 ;
    PORT
      LAYER met3 ;
        RECT 64.720 250.280 65.320 250.880 ;
    END
  END Tile_X0Y0_W1END[2]
  PIN Tile_X0Y0_W1END[3]
    DIRECTION INPUT ;
    USE SIGNAL ;
    ANTENNAGATEAREA 0.570000 ;
    PORT
      LAYER met3 ;
        RECT 64.720 251.640 65.320 252.240 ;
    END
  END Tile_X0Y0_W1END[3]
  PIN Tile_X0Y0_W2END[0]
    DIRECTION INPUT ;
    USE SIGNAL ;
    ANTENNAGATEAREA 1.308000 ;
    PORT
      LAYER met3 ;
        RECT 64.720 263.880 65.320 264.480 ;
    END
  END Tile_X0Y0_W2END[0]
  PIN Tile_X0Y0_W2END[1]
    DIRECTION INPUT ;
    USE SIGNAL ;
    ANTENNAGATEAREA 1.308000 ;
    PORT
      LAYER met3 ;
        RECT 64.720 265.240 65.320 265.840 ;
    END
  END Tile_X0Y0_W2END[1]
  PIN Tile_X0Y0_W2END[2]
    DIRECTION INPUT ;
    USE SIGNAL ;
    ANTENNAGATEAREA 1.308000 ;
    PORT
      LAYER met3 ;
        RECT 64.720 266.600 65.320 267.200 ;
    END
  END Tile_X0Y0_W2END[2]
  PIN Tile_X0Y0_W2END[3]
    DIRECTION INPUT ;
    USE SIGNAL ;
    ANTENNAGATEAREA 1.308000 ;
    PORT
      LAYER met3 ;
        RECT 64.720 267.960 65.320 268.560 ;
    END
  END Tile_X0Y0_W2END[3]
  PIN Tile_X0Y0_W2END[4]
    DIRECTION INPUT ;
    USE SIGNAL ;
    ANTENNAGATEAREA 1.396500 ;
    PORT
      LAYER met3 ;
        RECT 64.720 269.320 65.320 269.920 ;
    END
  END Tile_X0Y0_W2END[4]
  PIN Tile_X0Y0_W2END[5]
    DIRECTION INPUT ;
    USE SIGNAL ;
    ANTENNAGATEAREA 1.396500 ;
    PORT
      LAYER met3 ;
        RECT 64.720 270.680 65.320 271.280 ;
    END
  END Tile_X0Y0_W2END[5]
  PIN Tile_X0Y0_W2END[6]
    DIRECTION INPUT ;
    USE SIGNAL ;
    ANTENNAGATEAREA 0.901500 ;
    PORT
      LAYER met3 ;
        RECT 64.720 272.040 65.320 272.640 ;
    END
  END Tile_X0Y0_W2END[6]
  PIN Tile_X0Y0_W2END[7]
    DIRECTION INPUT ;
    USE SIGNAL ;
    ANTENNAGATEAREA 0.901500 ;
    PORT
      LAYER met3 ;
        RECT 64.720 273.400 65.320 274.000 ;
    END
  END Tile_X0Y0_W2END[7]
  PIN Tile_X0Y0_W2MID[0]
    DIRECTION INPUT ;
    USE SIGNAL ;
    ANTENNAGATEAREA 0.560700 ;
    ANTENNADIFFAREA 0.434700 ;
    PORT
      LAYER met3 ;
        RECT 64.720 253.000 65.320 253.600 ;
    END
  END Tile_X0Y0_W2MID[0]
  PIN Tile_X0Y0_W2MID[1]
    DIRECTION INPUT ;
    USE SIGNAL ;
    ANTENNAGATEAREA 0.126000 ;
    PORT
      LAYER met3 ;
        RECT 64.720 254.360 65.320 254.960 ;
    END
  END Tile_X0Y0_W2MID[1]
  PIN Tile_X0Y0_W2MID[2]
    DIRECTION INPUT ;
    USE SIGNAL ;
    ANTENNAGATEAREA 0.126000 ;
    PORT
      LAYER met3 ;
        RECT 64.720 255.720 65.320 256.320 ;
    END
  END Tile_X0Y0_W2MID[2]
  PIN Tile_X0Y0_W2MID[3]
    DIRECTION INPUT ;
    USE SIGNAL ;
    ANTENNAGATEAREA 0.126000 ;
    PORT
      LAYER met3 ;
        RECT 64.720 257.080 65.320 257.680 ;
    END
  END Tile_X0Y0_W2MID[3]
  PIN Tile_X0Y0_W2MID[4]
    DIRECTION INPUT ;
    USE SIGNAL ;
    ANTENNAGATEAREA 0.560700 ;
    ANTENNADIFFAREA 0.434700 ;
    PORT
      LAYER met3 ;
        RECT 64.720 258.440 65.320 259.040 ;
    END
  END Tile_X0Y0_W2MID[4]
  PIN Tile_X0Y0_W2MID[5]
    DIRECTION INPUT ;
    USE SIGNAL ;
    ANTENNAGATEAREA 0.126000 ;
    PORT
      LAYER met3 ;
        RECT 64.720 259.800 65.320 260.400 ;
    END
  END Tile_X0Y0_W2MID[5]
  PIN Tile_X0Y0_W2MID[6]
    DIRECTION INPUT ;
    USE SIGNAL ;
    ANTENNAGATEAREA 0.126000 ;
    PORT
      LAYER met3 ;
        RECT 64.720 261.160 65.320 261.760 ;
    END
  END Tile_X0Y0_W2MID[6]
  PIN Tile_X0Y0_W2MID[7]
    DIRECTION INPUT ;
    USE SIGNAL ;
    ANTENNAGATEAREA 0.560700 ;
    ANTENNADIFFAREA 0.434700 ;
    PORT
      LAYER met3 ;
        RECT 64.720 262.520 65.320 263.120 ;
    END
  END Tile_X0Y0_W2MID[7]
  PIN Tile_X0Y0_W6END[0]
    DIRECTION INPUT ;
    USE SIGNAL ;
    ANTENNAGATEAREA 0.663000 ;
    PORT
      LAYER met3 ;
        RECT 64.720 296.520 65.320 297.120 ;
    END
  END Tile_X0Y0_W6END[0]
  PIN Tile_X0Y0_W6END[10]
    DIRECTION INPUT ;
    USE SIGNAL ;
    ANTENNAGATEAREA 0.126000 ;
    PORT
      LAYER met3 ;
        RECT 64.720 310.120 65.320 310.720 ;
    END
  END Tile_X0Y0_W6END[10]
  PIN Tile_X0Y0_W6END[11]
    DIRECTION INPUT ;
    USE SIGNAL ;
    ANTENNAGATEAREA 0.845700 ;
    ANTENNADIFFAREA 0.434700 ;
    PORT
      LAYER met3 ;
        RECT 64.720 311.480 65.320 312.080 ;
    END
  END Tile_X0Y0_W6END[11]
  PIN Tile_X0Y0_W6END[1]
    DIRECTION INPUT ;
    USE SIGNAL ;
    ANTENNAGATEAREA 0.378000 ;
    PORT
      LAYER met3 ;
        RECT 64.720 297.880 65.320 298.480 ;
    END
  END Tile_X0Y0_W6END[1]
  PIN Tile_X0Y0_W6END[2]
    DIRECTION INPUT ;
    USE SIGNAL ;
    ANTENNAGATEAREA 0.378000 ;
    PORT
      LAYER met3 ;
        RECT 64.720 299.240 65.320 299.840 ;
    END
  END Tile_X0Y0_W6END[2]
  PIN Tile_X0Y0_W6END[3]
    DIRECTION INPUT ;
    USE SIGNAL ;
    ANTENNAGATEAREA 0.812700 ;
    ANTENNADIFFAREA 0.434700 ;
    PORT
      LAYER met3 ;
        RECT 64.720 300.600 65.320 301.200 ;
    END
  END Tile_X0Y0_W6END[3]
  PIN Tile_X0Y0_W6END[4]
    DIRECTION INPUT ;
    USE SIGNAL ;
    ANTENNAGATEAREA 0.411000 ;
    PORT
      LAYER met3 ;
        RECT 64.720 301.960 65.320 302.560 ;
    END
  END Tile_X0Y0_W6END[4]
  PIN Tile_X0Y0_W6END[5]
    DIRECTION INPUT ;
    USE SIGNAL ;
    ANTENNAGATEAREA 0.126000 ;
    PORT
      LAYER met3 ;
        RECT 64.720 303.320 65.320 303.920 ;
    END
  END Tile_X0Y0_W6END[5]
  PIN Tile_X0Y0_W6END[6]
    DIRECTION INPUT ;
    USE SIGNAL ;
    ANTENNAGATEAREA 1.121400 ;
    ANTENNADIFFAREA 0.869400 ;
    PORT
      LAYER met3 ;
        RECT 64.720 304.680 65.320 305.280 ;
    END
  END Tile_X0Y0_W6END[6]
  PIN Tile_X0Y0_W6END[7]
    DIRECTION INPUT ;
    USE SIGNAL ;
    ANTENNAGATEAREA 0.252000 ;
    PORT
      LAYER met3 ;
        RECT 64.720 306.040 65.320 306.640 ;
    END
  END Tile_X0Y0_W6END[7]
  PIN Tile_X0Y0_W6END[8]
    DIRECTION INPUT ;
    USE SIGNAL ;
    ANTENNAGATEAREA 0.537000 ;
    PORT
      LAYER met3 ;
        RECT 64.720 307.400 65.320 308.000 ;
    END
  END Tile_X0Y0_W6END[8]
  PIN Tile_X0Y0_W6END[9]
    DIRECTION INPUT ;
    USE SIGNAL ;
    ANTENNAGATEAREA 0.252000 ;
    PORT
      LAYER met3 ;
        RECT 64.720 308.760 65.320 309.360 ;
    END
  END Tile_X0Y0_W6END[9]
  PIN Tile_X0Y0_WW4END[0]
    DIRECTION INPUT ;
    USE SIGNAL ;
    ANTENNAGATEAREA 1.097700 ;
    ANTENNADIFFAREA 0.434700 ;
    PORT
      LAYER met3 ;
        RECT 64.720 274.760 65.320 275.360 ;
    END
  END Tile_X0Y0_WW4END[0]
  PIN Tile_X0Y0_WW4END[10]
    DIRECTION INPUT ;
    USE SIGNAL ;
    ANTENNAGATEAREA 0.906000 ;
    PORT
      LAYER met3 ;
        RECT 64.720 288.360 65.320 288.960 ;
    END
  END Tile_X0Y0_WW4END[10]
  PIN Tile_X0Y0_WW4END[11]
    DIRECTION INPUT ;
    USE SIGNAL ;
    ANTENNAGATEAREA 0.906000 ;
    PORT
      LAYER met3 ;
        RECT 64.720 289.720 65.320 290.320 ;
    END
  END Tile_X0Y0_WW4END[11]
  PIN Tile_X0Y0_WW4END[12]
    DIRECTION INPUT ;
    USE SIGNAL ;
    ANTENNAGATEAREA 1.340700 ;
    ANTENNADIFFAREA 0.434700 ;
    PORT
      LAYER met3 ;
        RECT 64.720 291.080 65.320 291.680 ;
    END
  END Tile_X0Y0_WW4END[12]
  PIN Tile_X0Y0_WW4END[13]
    DIRECTION INPUT ;
    USE SIGNAL ;
    ANTENNAGATEAREA 0.906000 ;
    PORT
      LAYER met3 ;
        RECT 64.720 292.440 65.320 293.040 ;
    END
  END Tile_X0Y0_WW4END[13]
  PIN Tile_X0Y0_WW4END[14]
    DIRECTION INPUT ;
    USE SIGNAL ;
    ANTENNAGATEAREA 0.906000 ;
    PORT
      LAYER met3 ;
        RECT 64.720 293.800 65.320 294.400 ;
    END
  END Tile_X0Y0_WW4END[14]
  PIN Tile_X0Y0_WW4END[15]
    DIRECTION INPUT ;
    USE SIGNAL ;
    ANTENNAGATEAREA 0.906000 ;
    PORT
      LAYER met3 ;
        RECT 64.720 295.160 65.320 295.760 ;
    END
  END Tile_X0Y0_WW4END[15]
  PIN Tile_X0Y0_WW4END[1]
    DIRECTION INPUT ;
    USE SIGNAL ;
    ANTENNAGATEAREA 0.663000 ;
    PORT
      LAYER met3 ;
        RECT 64.720 276.120 65.320 276.720 ;
    END
  END Tile_X0Y0_WW4END[1]
  PIN Tile_X0Y0_WW4END[2]
    DIRECTION INPUT ;
    USE SIGNAL ;
    ANTENNAGATEAREA 0.663000 ;
    PORT
      LAYER met3 ;
        RECT 64.720 277.480 65.320 278.080 ;
    END
  END Tile_X0Y0_WW4END[2]
  PIN Tile_X0Y0_WW4END[3]
    DIRECTION INPUT ;
    USE SIGNAL ;
    ANTENNAGATEAREA 0.663000 ;
    PORT
      LAYER met3 ;
        RECT 64.720 278.840 65.320 279.440 ;
    END
  END Tile_X0Y0_WW4END[3]
  PIN Tile_X0Y0_WW4END[4]
    DIRECTION INPUT ;
    USE SIGNAL ;
    ANTENNAGATEAREA 0.537000 ;
    PORT
      LAYER met3 ;
        RECT 64.720 280.200 65.320 280.800 ;
    END
  END Tile_X0Y0_WW4END[4]
  PIN Tile_X0Y0_WW4END[5]
    DIRECTION INPUT ;
    USE SIGNAL ;
    ANTENNAGATEAREA 0.537000 ;
    PORT
      LAYER met3 ;
        RECT 64.720 281.560 65.320 282.160 ;
    END
  END Tile_X0Y0_WW4END[5]
  PIN Tile_X0Y0_WW4END[6]
    DIRECTION INPUT ;
    USE SIGNAL ;
    ANTENNAGATEAREA 0.537000 ;
    PORT
      LAYER met3 ;
        RECT 64.720 282.920 65.320 283.520 ;
    END
  END Tile_X0Y0_WW4END[6]
  PIN Tile_X0Y0_WW4END[7]
    DIRECTION INPUT ;
    USE SIGNAL ;
    ANTENNAGATEAREA 0.537000 ;
    PORT
      LAYER met3 ;
        RECT 64.720 284.280 65.320 284.880 ;
    END
  END Tile_X0Y0_WW4END[7]
  PIN Tile_X0Y0_WW4END[8]
    DIRECTION INPUT ;
    USE SIGNAL ;
    ANTENNAGATEAREA 0.906000 ;
    PORT
      LAYER met3 ;
        RECT 64.720 285.640 65.320 286.240 ;
    END
  END Tile_X0Y0_WW4END[8]
  PIN Tile_X0Y0_WW4END[9]
    DIRECTION INPUT ;
    USE SIGNAL ;
    ANTENNAGATEAREA 0.906000 ;
    PORT
      LAYER met3 ;
        RECT 64.720 287.000 65.320 287.600 ;
    END
  END Tile_X0Y0_WW4END[9]
  PIN Tile_X0Y1_E1BEG[0]
    DIRECTION OUTPUT ;
    USE SIGNAL ;
    ANTENNADIFFAREA 0.702900 ;
    PORT
      LAYER met3 ;
        RECT 64.720 89.800 65.320 90.400 ;
    END
  END Tile_X0Y1_E1BEG[0]
  PIN Tile_X0Y1_E1BEG[1]
    DIRECTION OUTPUT ;
    USE SIGNAL ;
    ANTENNADIFFAREA 0.702900 ;
    PORT
      LAYER met3 ;
        RECT 64.720 91.160 65.320 91.760 ;
    END
  END Tile_X0Y1_E1BEG[1]
  PIN Tile_X0Y1_E1BEG[2]
    DIRECTION OUTPUT ;
    USE SIGNAL ;
    ANTENNADIFFAREA 0.702900 ;
    PORT
      LAYER met3 ;
        RECT 64.720 92.520 65.320 93.120 ;
    END
  END Tile_X0Y1_E1BEG[2]
  PIN Tile_X0Y1_E1BEG[3]
    DIRECTION OUTPUT ;
    USE SIGNAL ;
    ANTENNADIFFAREA 0.702900 ;
    PORT
      LAYER met3 ;
        RECT 64.720 93.880 65.320 94.480 ;
    END
  END Tile_X0Y1_E1BEG[3]
  PIN Tile_X0Y1_E2BEG[0]
    DIRECTION OUTPUT ;
    USE SIGNAL ;
    ANTENNADIFFAREA 0.702900 ;
    PORT
      LAYER met3 ;
        RECT 64.720 95.240 65.320 95.840 ;
    END
  END Tile_X0Y1_E2BEG[0]
  PIN Tile_X0Y1_E2BEG[1]
    DIRECTION OUTPUT ;
    USE SIGNAL ;
    ANTENNADIFFAREA 0.702900 ;
    PORT
      LAYER met3 ;
        RECT 64.720 96.600 65.320 97.200 ;
    END
  END Tile_X0Y1_E2BEG[1]
  PIN Tile_X0Y1_E2BEG[2]
    DIRECTION OUTPUT ;
    USE SIGNAL ;
    ANTENNADIFFAREA 0.702900 ;
    PORT
      LAYER met3 ;
        RECT 64.720 97.960 65.320 98.560 ;
    END
  END Tile_X0Y1_E2BEG[2]
  PIN Tile_X0Y1_E2BEG[3]
    DIRECTION OUTPUT ;
    USE SIGNAL ;
    ANTENNADIFFAREA 0.702900 ;
    PORT
      LAYER met3 ;
        RECT 64.720 99.320 65.320 99.920 ;
    END
  END Tile_X0Y1_E2BEG[3]
  PIN Tile_X0Y1_E2BEG[4]
    DIRECTION OUTPUT ;
    USE SIGNAL ;
    ANTENNADIFFAREA 0.702900 ;
    PORT
      LAYER met3 ;
        RECT 64.720 100.680 65.320 101.280 ;
    END
  END Tile_X0Y1_E2BEG[4]
  PIN Tile_X0Y1_E2BEG[5]
    DIRECTION OUTPUT ;
    USE SIGNAL ;
    ANTENNADIFFAREA 0.702900 ;
    PORT
      LAYER met3 ;
        RECT 64.720 102.040 65.320 102.640 ;
    END
  END Tile_X0Y1_E2BEG[5]
  PIN Tile_X0Y1_E2BEG[6]
    DIRECTION OUTPUT ;
    USE SIGNAL ;
    ANTENNADIFFAREA 0.702900 ;
    PORT
      LAYER met3 ;
        RECT 64.720 103.400 65.320 104.000 ;
    END
  END Tile_X0Y1_E2BEG[6]
  PIN Tile_X0Y1_E2BEG[7]
    DIRECTION OUTPUT ;
    USE SIGNAL ;
    ANTENNADIFFAREA 0.702900 ;
    PORT
      LAYER met3 ;
        RECT 64.720 104.760 65.320 105.360 ;
    END
  END Tile_X0Y1_E2BEG[7]
  PIN Tile_X0Y1_E2BEGb[0]
    DIRECTION OUTPUT ;
    USE SIGNAL ;
    ANTENNADIFFAREA 0.702900 ;
    PORT
      LAYER met3 ;
        RECT 64.720 106.120 65.320 106.720 ;
    END
  END Tile_X0Y1_E2BEGb[0]
  PIN Tile_X0Y1_E2BEGb[1]
    DIRECTION OUTPUT ;
    USE SIGNAL ;
    ANTENNADIFFAREA 0.702900 ;
    PORT
      LAYER met3 ;
        RECT 64.720 107.480 65.320 108.080 ;
    END
  END Tile_X0Y1_E2BEGb[1]
  PIN Tile_X0Y1_E2BEGb[2]
    DIRECTION OUTPUT ;
    USE SIGNAL ;
    ANTENNADIFFAREA 0.702900 ;
    PORT
      LAYER met3 ;
        RECT 64.720 108.840 65.320 109.440 ;
    END
  END Tile_X0Y1_E2BEGb[2]
  PIN Tile_X0Y1_E2BEGb[3]
    DIRECTION OUTPUT ;
    USE SIGNAL ;
    ANTENNADIFFAREA 0.702900 ;
    PORT
      LAYER met3 ;
        RECT 64.720 110.200 65.320 110.800 ;
    END
  END Tile_X0Y1_E2BEGb[3]
  PIN Tile_X0Y1_E2BEGb[4]
    DIRECTION OUTPUT ;
    USE SIGNAL ;
    ANTENNADIFFAREA 0.702900 ;
    PORT
      LAYER met3 ;
        RECT 64.720 111.560 65.320 112.160 ;
    END
  END Tile_X0Y1_E2BEGb[4]
  PIN Tile_X0Y1_E2BEGb[5]
    DIRECTION OUTPUT ;
    USE SIGNAL ;
    ANTENNADIFFAREA 0.702900 ;
    PORT
      LAYER met3 ;
        RECT 64.720 112.920 65.320 113.520 ;
    END
  END Tile_X0Y1_E2BEGb[5]
  PIN Tile_X0Y1_E2BEGb[6]
    DIRECTION OUTPUT ;
    USE SIGNAL ;
    ANTENNADIFFAREA 0.702900 ;
    PORT
      LAYER met3 ;
        RECT 64.720 114.280 65.320 114.880 ;
    END
  END Tile_X0Y1_E2BEGb[6]
  PIN Tile_X0Y1_E2BEGb[7]
    DIRECTION OUTPUT ;
    USE SIGNAL ;
    ANTENNADIFFAREA 0.702900 ;
    PORT
      LAYER met3 ;
        RECT 64.720 115.640 65.320 116.240 ;
    END
  END Tile_X0Y1_E2BEGb[7]
  PIN Tile_X0Y1_E6BEG[0]
    DIRECTION OUTPUT ;
    USE SIGNAL ;
    ANTENNADIFFAREA 0.702900 ;
    PORT
      LAYER met3 ;
        RECT 64.720 138.760 65.320 139.360 ;
    END
  END Tile_X0Y1_E6BEG[0]
  PIN Tile_X0Y1_E6BEG[10]
    DIRECTION OUTPUT ;
    USE SIGNAL ;
    ANTENNADIFFAREA 0.702900 ;
    PORT
      LAYER met3 ;
        RECT 64.720 152.360 65.320 152.960 ;
    END
  END Tile_X0Y1_E6BEG[10]
  PIN Tile_X0Y1_E6BEG[11]
    DIRECTION OUTPUT ;
    USE SIGNAL ;
    ANTENNADIFFAREA 0.702900 ;
    PORT
      LAYER met3 ;
        RECT 64.720 153.720 65.320 154.320 ;
    END
  END Tile_X0Y1_E6BEG[11]
  PIN Tile_X0Y1_E6BEG[1]
    DIRECTION OUTPUT ;
    USE SIGNAL ;
    ANTENNADIFFAREA 0.702900 ;
    PORT
      LAYER met3 ;
        RECT 64.720 140.120 65.320 140.720 ;
    END
  END Tile_X0Y1_E6BEG[1]
  PIN Tile_X0Y1_E6BEG[2]
    DIRECTION OUTPUT ;
    USE SIGNAL ;
    ANTENNADIFFAREA 0.702900 ;
    PORT
      LAYER met3 ;
        RECT 64.720 141.480 65.320 142.080 ;
    END
  END Tile_X0Y1_E6BEG[2]
  PIN Tile_X0Y1_E6BEG[3]
    DIRECTION OUTPUT ;
    USE SIGNAL ;
    ANTENNADIFFAREA 0.702900 ;
    PORT
      LAYER met3 ;
        RECT 64.720 142.840 65.320 143.440 ;
    END
  END Tile_X0Y1_E6BEG[3]
  PIN Tile_X0Y1_E6BEG[4]
    DIRECTION OUTPUT ;
    USE SIGNAL ;
    ANTENNADIFFAREA 0.702900 ;
    PORT
      LAYER met3 ;
        RECT 64.720 144.200 65.320 144.800 ;
    END
  END Tile_X0Y1_E6BEG[4]
  PIN Tile_X0Y1_E6BEG[5]
    DIRECTION OUTPUT ;
    USE SIGNAL ;
    ANTENNADIFFAREA 0.702900 ;
    PORT
      LAYER met3 ;
        RECT 64.720 145.560 65.320 146.160 ;
    END
  END Tile_X0Y1_E6BEG[5]
  PIN Tile_X0Y1_E6BEG[6]
    DIRECTION OUTPUT ;
    USE SIGNAL ;
    ANTENNADIFFAREA 0.702900 ;
    PORT
      LAYER met3 ;
        RECT 64.720 146.920 65.320 147.520 ;
    END
  END Tile_X0Y1_E6BEG[6]
  PIN Tile_X0Y1_E6BEG[7]
    DIRECTION OUTPUT ;
    USE SIGNAL ;
    ANTENNADIFFAREA 0.702900 ;
    PORT
      LAYER met3 ;
        RECT 64.720 148.280 65.320 148.880 ;
    END
  END Tile_X0Y1_E6BEG[7]
  PIN Tile_X0Y1_E6BEG[8]
    DIRECTION OUTPUT ;
    USE SIGNAL ;
    ANTENNADIFFAREA 0.702900 ;
    PORT
      LAYER met3 ;
        RECT 64.720 149.640 65.320 150.240 ;
    END
  END Tile_X0Y1_E6BEG[8]
  PIN Tile_X0Y1_E6BEG[9]
    DIRECTION OUTPUT ;
    USE SIGNAL ;
    ANTENNADIFFAREA 0.702900 ;
    PORT
      LAYER met3 ;
        RECT 64.720 151.000 65.320 151.600 ;
    END
  END Tile_X0Y1_E6BEG[9]
  PIN Tile_X0Y1_EE4BEG[0]
    DIRECTION OUTPUT ;
    USE SIGNAL ;
    ANTENNADIFFAREA 0.702900 ;
    PORT
      LAYER met3 ;
        RECT 64.720 117.000 65.320 117.600 ;
    END
  END Tile_X0Y1_EE4BEG[0]
  PIN Tile_X0Y1_EE4BEG[10]
    DIRECTION OUTPUT ;
    USE SIGNAL ;
    ANTENNADIFFAREA 0.702900 ;
    PORT
      LAYER met3 ;
        RECT 64.720 130.600 65.320 131.200 ;
    END
  END Tile_X0Y1_EE4BEG[10]
  PIN Tile_X0Y1_EE4BEG[11]
    DIRECTION OUTPUT ;
    USE SIGNAL ;
    ANTENNADIFFAREA 0.702900 ;
    PORT
      LAYER met3 ;
        RECT 64.720 131.960 65.320 132.560 ;
    END
  END Tile_X0Y1_EE4BEG[11]
  PIN Tile_X0Y1_EE4BEG[12]
    DIRECTION OUTPUT ;
    USE SIGNAL ;
    ANTENNADIFFAREA 0.702900 ;
    PORT
      LAYER met3 ;
        RECT 64.720 133.320 65.320 133.920 ;
    END
  END Tile_X0Y1_EE4BEG[12]
  PIN Tile_X0Y1_EE4BEG[13]
    DIRECTION OUTPUT ;
    USE SIGNAL ;
    ANTENNADIFFAREA 0.702900 ;
    PORT
      LAYER met3 ;
        RECT 64.720 134.680 65.320 135.280 ;
    END
  END Tile_X0Y1_EE4BEG[13]
  PIN Tile_X0Y1_EE4BEG[14]
    DIRECTION OUTPUT ;
    USE SIGNAL ;
    ANTENNADIFFAREA 0.702900 ;
    PORT
      LAYER met3 ;
        RECT 64.720 136.040 65.320 136.640 ;
    END
  END Tile_X0Y1_EE4BEG[14]
  PIN Tile_X0Y1_EE4BEG[15]
    DIRECTION OUTPUT ;
    USE SIGNAL ;
    ANTENNADIFFAREA 0.702900 ;
    PORT
      LAYER met3 ;
        RECT 64.720 137.400 65.320 138.000 ;
    END
  END Tile_X0Y1_EE4BEG[15]
  PIN Tile_X0Y1_EE4BEG[1]
    DIRECTION OUTPUT ;
    USE SIGNAL ;
    ANTENNADIFFAREA 0.702900 ;
    PORT
      LAYER met3 ;
        RECT 64.720 118.360 65.320 118.960 ;
    END
  END Tile_X0Y1_EE4BEG[1]
  PIN Tile_X0Y1_EE4BEG[2]
    DIRECTION OUTPUT ;
    USE SIGNAL ;
    ANTENNADIFFAREA 0.702900 ;
    PORT
      LAYER met3 ;
        RECT 64.720 119.720 65.320 120.320 ;
    END
  END Tile_X0Y1_EE4BEG[2]
  PIN Tile_X0Y1_EE4BEG[3]
    DIRECTION OUTPUT ;
    USE SIGNAL ;
    ANTENNADIFFAREA 0.702900 ;
    PORT
      LAYER met3 ;
        RECT 64.720 121.080 65.320 121.680 ;
    END
  END Tile_X0Y1_EE4BEG[3]
  PIN Tile_X0Y1_EE4BEG[4]
    DIRECTION OUTPUT ;
    USE SIGNAL ;
    ANTENNADIFFAREA 0.702900 ;
    PORT
      LAYER met3 ;
        RECT 64.720 122.440 65.320 123.040 ;
    END
  END Tile_X0Y1_EE4BEG[4]
  PIN Tile_X0Y1_EE4BEG[5]
    DIRECTION OUTPUT ;
    USE SIGNAL ;
    ANTENNADIFFAREA 0.702900 ;
    PORT
      LAYER met3 ;
        RECT 64.720 123.800 65.320 124.400 ;
    END
  END Tile_X0Y1_EE4BEG[5]
  PIN Tile_X0Y1_EE4BEG[6]
    DIRECTION OUTPUT ;
    USE SIGNAL ;
    ANTENNADIFFAREA 0.702900 ;
    PORT
      LAYER met3 ;
        RECT 64.720 125.160 65.320 125.760 ;
    END
  END Tile_X0Y1_EE4BEG[6]
  PIN Tile_X0Y1_EE4BEG[7]
    DIRECTION OUTPUT ;
    USE SIGNAL ;
    ANTENNADIFFAREA 0.702900 ;
    PORT
      LAYER met3 ;
        RECT 64.720 126.520 65.320 127.120 ;
    END
  END Tile_X0Y1_EE4BEG[7]
  PIN Tile_X0Y1_EE4BEG[8]
    DIRECTION OUTPUT ;
    USE SIGNAL ;
    ANTENNADIFFAREA 0.702900 ;
    PORT
      LAYER met3 ;
        RECT 64.720 127.880 65.320 128.480 ;
    END
  END Tile_X0Y1_EE4BEG[8]
  PIN Tile_X0Y1_EE4BEG[9]
    DIRECTION OUTPUT ;
    USE SIGNAL ;
    ANTENNADIFFAREA 0.702900 ;
    PORT
      LAYER met3 ;
        RECT 64.720 129.240 65.320 129.840 ;
    END
  END Tile_X0Y1_EE4BEG[9]
  PIN Tile_X0Y1_FrameData[0]
    DIRECTION INPUT ;
    USE SIGNAL ;
    ANTENNAGATEAREA 1.664400 ;
    ANTENNADIFFAREA 0.869400 ;
    PORT
      LAYER met3 ;
        RECT 0.000 157.800 0.600 158.400 ;
    END
  END Tile_X0Y1_FrameData[0]
  PIN Tile_X0Y1_FrameData[10]
    DIRECTION INPUT ;
    USE SIGNAL ;
    ANTENNAGATEAREA 0.795000 ;
    PORT
      LAYER met3 ;
        RECT 0.000 198.600 0.600 199.200 ;
    END
  END Tile_X0Y1_FrameData[10]
  PIN Tile_X0Y1_FrameData[11]
    DIRECTION INPUT ;
    USE SIGNAL ;
    ANTENNAGATEAREA 0.795000 ;
    PORT
      LAYER met3 ;
        RECT 0.000 202.680 0.600 203.280 ;
    END
  END Tile_X0Y1_FrameData[11]
  PIN Tile_X0Y1_FrameData[12]
    DIRECTION INPUT ;
    USE SIGNAL ;
    ANTENNAGATEAREA 0.795000 ;
    PORT
      LAYER met3 ;
        RECT 0.000 206.760 0.600 207.360 ;
    END
  END Tile_X0Y1_FrameData[12]
  PIN Tile_X0Y1_FrameData[13]
    DIRECTION INPUT ;
    USE SIGNAL ;
    ANTENNAGATEAREA 0.795000 ;
    PORT
      LAYER met3 ;
        RECT 0.000 210.840 0.600 211.440 ;
    END
  END Tile_X0Y1_FrameData[13]
  PIN Tile_X0Y1_FrameData[14]
    DIRECTION INPUT ;
    USE SIGNAL ;
    ANTENNAGATEAREA 0.795000 ;
    PORT
      LAYER met3 ;
        RECT 0.000 214.920 0.600 215.520 ;
    END
  END Tile_X0Y1_FrameData[14]
  PIN Tile_X0Y1_FrameData[15]
    DIRECTION INPUT ;
    USE SIGNAL ;
    ANTENNAGATEAREA 0.795000 ;
    PORT
      LAYER met3 ;
        RECT 0.000 219.000 0.600 219.600 ;
    END
  END Tile_X0Y1_FrameData[15]
  PIN Tile_X0Y1_FrameData[16]
    DIRECTION INPUT ;
    USE SIGNAL ;
    ANTENNAGATEAREA 1.229700 ;
    ANTENNADIFFAREA 0.434700 ;
    PORT
      LAYER met3 ;
        RECT 0.000 223.080 0.600 223.680 ;
    END
  END Tile_X0Y1_FrameData[16]
  PIN Tile_X0Y1_FrameData[17]
    DIRECTION INPUT ;
    USE SIGNAL ;
    ANTENNAGATEAREA 0.795000 ;
    PORT
      LAYER met3 ;
        RECT 0.000 227.160 0.600 227.760 ;
    END
  END Tile_X0Y1_FrameData[17]
  PIN Tile_X0Y1_FrameData[18]
    DIRECTION INPUT ;
    USE SIGNAL ;
    ANTENNAGATEAREA 1.229700 ;
    ANTENNADIFFAREA 0.434700 ;
    PORT
      LAYER met3 ;
        RECT 0.000 231.240 0.600 231.840 ;
    END
  END Tile_X0Y1_FrameData[18]
  PIN Tile_X0Y1_FrameData[19]
    DIRECTION INPUT ;
    USE SIGNAL ;
    ANTENNAGATEAREA 1.388700 ;
    ANTENNADIFFAREA 0.434700 ;
    PORT
      LAYER met3 ;
        RECT 0.000 235.320 0.600 235.920 ;
    END
  END Tile_X0Y1_FrameData[19]
  PIN Tile_X0Y1_FrameData[1]
    DIRECTION INPUT ;
    USE SIGNAL ;
    ANTENNAGATEAREA 0.795000 ;
    PORT
      LAYER met3 ;
        RECT 0.000 161.880 0.600 162.480 ;
    END
  END Tile_X0Y1_FrameData[1]
  PIN Tile_X0Y1_FrameData[20]
    DIRECTION INPUT ;
    USE SIGNAL ;
    ANTENNAGATEAREA 0.954000 ;
    PORT
      LAYER met3 ;
        RECT 0.000 239.400 0.600 240.000 ;
    END
  END Tile_X0Y1_FrameData[20]
  PIN Tile_X0Y1_FrameData[21]
    DIRECTION INPUT ;
    USE SIGNAL ;
    ANTENNAGATEAREA 1.388700 ;
    ANTENNADIFFAREA 0.434700 ;
    PORT
      LAYER met3 ;
        RECT 0.000 243.480 0.600 244.080 ;
    END
  END Tile_X0Y1_FrameData[21]
  PIN Tile_X0Y1_FrameData[22]
    DIRECTION INPUT ;
    USE SIGNAL ;
    ANTENNAGATEAREA 0.954000 ;
    PORT
      LAYER met3 ;
        RECT 0.000 247.560 0.600 248.160 ;
    END
  END Tile_X0Y1_FrameData[22]
  PIN Tile_X0Y1_FrameData[23]
    DIRECTION INPUT ;
    USE SIGNAL ;
    ANTENNAGATEAREA 0.954000 ;
    PORT
      LAYER met3 ;
        RECT 0.000 251.640 0.600 252.240 ;
    END
  END Tile_X0Y1_FrameData[23]
  PIN Tile_X0Y1_FrameData[24]
    DIRECTION INPUT ;
    USE SIGNAL ;
    ANTENNAGATEAREA 0.954000 ;
    PORT
      LAYER met3 ;
        RECT 0.000 255.720 0.600 256.320 ;
    END
  END Tile_X0Y1_FrameData[24]
  PIN Tile_X0Y1_FrameData[25]
    DIRECTION INPUT ;
    USE SIGNAL ;
    ANTENNAGATEAREA 0.954000 ;
    PORT
      LAYER met3 ;
        RECT 0.000 259.800 0.600 260.400 ;
    END
  END Tile_X0Y1_FrameData[25]
  PIN Tile_X0Y1_FrameData[26]
    DIRECTION INPUT ;
    USE SIGNAL ;
    ANTENNAGATEAREA 0.954000 ;
    PORT
      LAYER met3 ;
        RECT 0.000 263.880 0.600 264.480 ;
    END
  END Tile_X0Y1_FrameData[26]
  PIN Tile_X0Y1_FrameData[27]
    DIRECTION INPUT ;
    USE SIGNAL ;
    ANTENNAGATEAREA 0.954000 ;
    PORT
      LAYER met3 ;
        RECT 0.000 267.960 0.600 268.560 ;
    END
  END Tile_X0Y1_FrameData[27]
  PIN Tile_X0Y1_FrameData[28]
    DIRECTION INPUT ;
    USE SIGNAL ;
    ANTENNAGATEAREA 0.954000 ;
    PORT
      LAYER met3 ;
        RECT 0.000 272.040 0.600 272.640 ;
    END
  END Tile_X0Y1_FrameData[28]
  PIN Tile_X0Y1_FrameData[29]
    DIRECTION INPUT ;
    USE SIGNAL ;
    ANTENNAGATEAREA 0.954000 ;
    PORT
      LAYER met3 ;
        RECT 0.000 276.120 0.600 276.720 ;
    END
  END Tile_X0Y1_FrameData[29]
  PIN Tile_X0Y1_FrameData[2]
    DIRECTION INPUT ;
    USE SIGNAL ;
    ANTENNAGATEAREA 0.795000 ;
    PORT
      LAYER met3 ;
        RECT 0.000 165.960 0.600 166.560 ;
    END
  END Tile_X0Y1_FrameData[2]
  PIN Tile_X0Y1_FrameData[30]
    DIRECTION INPUT ;
    USE SIGNAL ;
    ANTENNAGATEAREA 0.954000 ;
    PORT
      LAYER met3 ;
        RECT 0.000 280.200 0.600 280.800 ;
    END
  END Tile_X0Y1_FrameData[30]
  PIN Tile_X0Y1_FrameData[31]
    DIRECTION INPUT ;
    USE SIGNAL ;
    ANTENNAGATEAREA 1.388700 ;
    ANTENNADIFFAREA 0.434700 ;
    PORT
      LAYER met3 ;
        RECT 0.000 284.280 0.600 284.880 ;
    END
  END Tile_X0Y1_FrameData[31]
  PIN Tile_X0Y1_FrameData[3]
    DIRECTION INPUT ;
    USE SIGNAL ;
    ANTENNAGATEAREA 2.099100 ;
    ANTENNADIFFAREA 1.304100 ;
    PORT
      LAYER met3 ;
        RECT 0.000 170.040 0.600 170.640 ;
    END
  END Tile_X0Y1_FrameData[3]
  PIN Tile_X0Y1_FrameData[4]
    DIRECTION INPUT ;
    USE SIGNAL ;
    ANTENNAGATEAREA 2.099100 ;
    ANTENNADIFFAREA 1.304100 ;
    PORT
      LAYER met3 ;
        RECT 0.000 174.120 0.600 174.720 ;
    END
  END Tile_X0Y1_FrameData[4]
  PIN Tile_X0Y1_FrameData[5]
    DIRECTION INPUT ;
    USE SIGNAL ;
    ANTENNAGATEAREA 0.795000 ;
    PORT
      LAYER met3 ;
        RECT 0.000 178.200 0.600 178.800 ;
    END
  END Tile_X0Y1_FrameData[5]
  PIN Tile_X0Y1_FrameData[6]
    DIRECTION INPUT ;
    USE SIGNAL ;
    ANTENNAGATEAREA 0.795000 ;
    PORT
      LAYER met3 ;
        RECT 0.000 182.280 0.600 182.880 ;
    END
  END Tile_X0Y1_FrameData[6]
  PIN Tile_X0Y1_FrameData[7]
    DIRECTION INPUT ;
    USE SIGNAL ;
    ANTENNAGATEAREA 0.795000 ;
    PORT
      LAYER met3 ;
        RECT 0.000 186.360 0.600 186.960 ;
    END
  END Tile_X0Y1_FrameData[7]
  PIN Tile_X0Y1_FrameData[8]
    DIRECTION INPUT ;
    USE SIGNAL ;
    ANTENNAGATEAREA 0.795000 ;
    PORT
      LAYER met3 ;
        RECT 0.000 190.440 0.600 191.040 ;
    END
  END Tile_X0Y1_FrameData[8]
  PIN Tile_X0Y1_FrameData[9]
    DIRECTION INPUT ;
    USE SIGNAL ;
    ANTENNAGATEAREA 0.795000 ;
    PORT
      LAYER met3 ;
        RECT 0.000 194.520 0.600 195.120 ;
    END
  END Tile_X0Y1_FrameData[9]
  PIN Tile_X0Y1_FrameData_O[0]
    DIRECTION OUTPUT ;
    USE SIGNAL ;
    ANTENNADIFFAREA 0.702900 ;
    PORT
      LAYER met3 ;
        RECT 64.720 155.080 65.320 155.680 ;
    END
  END Tile_X0Y1_FrameData_O[0]
  PIN Tile_X0Y1_FrameData_O[10]
    DIRECTION OUTPUT ;
    USE SIGNAL ;
    ANTENNADIFFAREA 0.702900 ;
    PORT
      LAYER met3 ;
        RECT 64.720 168.680 65.320 169.280 ;
    END
  END Tile_X0Y1_FrameData_O[10]
  PIN Tile_X0Y1_FrameData_O[11]
    DIRECTION OUTPUT ;
    USE SIGNAL ;
    ANTENNADIFFAREA 0.702900 ;
    PORT
      LAYER met3 ;
        RECT 64.720 170.040 65.320 170.640 ;
    END
  END Tile_X0Y1_FrameData_O[11]
  PIN Tile_X0Y1_FrameData_O[12]
    DIRECTION OUTPUT ;
    USE SIGNAL ;
    ANTENNADIFFAREA 0.702900 ;
    PORT
      LAYER met3 ;
        RECT 64.720 171.400 65.320 172.000 ;
    END
  END Tile_X0Y1_FrameData_O[12]
  PIN Tile_X0Y1_FrameData_O[13]
    DIRECTION OUTPUT ;
    USE SIGNAL ;
    ANTENNADIFFAREA 0.702900 ;
    PORT
      LAYER met3 ;
        RECT 64.720 172.760 65.320 173.360 ;
    END
  END Tile_X0Y1_FrameData_O[13]
  PIN Tile_X0Y1_FrameData_O[14]
    DIRECTION OUTPUT ;
    USE SIGNAL ;
    ANTENNADIFFAREA 0.702900 ;
    PORT
      LAYER met3 ;
        RECT 64.720 174.120 65.320 174.720 ;
    END
  END Tile_X0Y1_FrameData_O[14]
  PIN Tile_X0Y1_FrameData_O[15]
    DIRECTION OUTPUT ;
    USE SIGNAL ;
    ANTENNADIFFAREA 0.702900 ;
    PORT
      LAYER met3 ;
        RECT 64.720 175.480 65.320 176.080 ;
    END
  END Tile_X0Y1_FrameData_O[15]
  PIN Tile_X0Y1_FrameData_O[16]
    DIRECTION OUTPUT ;
    USE SIGNAL ;
    ANTENNADIFFAREA 0.702900 ;
    PORT
      LAYER met3 ;
        RECT 64.720 176.840 65.320 177.440 ;
    END
  END Tile_X0Y1_FrameData_O[16]
  PIN Tile_X0Y1_FrameData_O[17]
    DIRECTION OUTPUT ;
    USE SIGNAL ;
    ANTENNADIFFAREA 0.702900 ;
    PORT
      LAYER met3 ;
        RECT 64.720 178.200 65.320 178.800 ;
    END
  END Tile_X0Y1_FrameData_O[17]
  PIN Tile_X0Y1_FrameData_O[18]
    DIRECTION OUTPUT ;
    USE SIGNAL ;
    ANTENNADIFFAREA 0.702900 ;
    PORT
      LAYER met3 ;
        RECT 64.720 179.560 65.320 180.160 ;
    END
  END Tile_X0Y1_FrameData_O[18]
  PIN Tile_X0Y1_FrameData_O[19]
    DIRECTION OUTPUT ;
    USE SIGNAL ;
    ANTENNADIFFAREA 0.702900 ;
    PORT
      LAYER met3 ;
        RECT 64.720 180.920 65.320 181.520 ;
    END
  END Tile_X0Y1_FrameData_O[19]
  PIN Tile_X0Y1_FrameData_O[1]
    DIRECTION OUTPUT ;
    USE SIGNAL ;
    ANTENNADIFFAREA 0.702900 ;
    PORT
      LAYER met3 ;
        RECT 64.720 156.440 65.320 157.040 ;
    END
  END Tile_X0Y1_FrameData_O[1]
  PIN Tile_X0Y1_FrameData_O[20]
    DIRECTION OUTPUT ;
    USE SIGNAL ;
    ANTENNADIFFAREA 0.702900 ;
    PORT
      LAYER met3 ;
        RECT 64.720 182.280 65.320 182.880 ;
    END
  END Tile_X0Y1_FrameData_O[20]
  PIN Tile_X0Y1_FrameData_O[21]
    DIRECTION OUTPUT ;
    USE SIGNAL ;
    ANTENNADIFFAREA 0.702900 ;
    PORT
      LAYER met3 ;
        RECT 64.720 183.640 65.320 184.240 ;
    END
  END Tile_X0Y1_FrameData_O[21]
  PIN Tile_X0Y1_FrameData_O[22]
    DIRECTION OUTPUT ;
    USE SIGNAL ;
    ANTENNADIFFAREA 0.702900 ;
    PORT
      LAYER met3 ;
        RECT 64.720 185.000 65.320 185.600 ;
    END
  END Tile_X0Y1_FrameData_O[22]
  PIN Tile_X0Y1_FrameData_O[23]
    DIRECTION OUTPUT ;
    USE SIGNAL ;
    ANTENNADIFFAREA 0.702900 ;
    PORT
      LAYER met3 ;
        RECT 64.720 186.360 65.320 186.960 ;
    END
  END Tile_X0Y1_FrameData_O[23]
  PIN Tile_X0Y1_FrameData_O[24]
    DIRECTION OUTPUT ;
    USE SIGNAL ;
    ANTENNADIFFAREA 0.702900 ;
    PORT
      LAYER met3 ;
        RECT 64.720 187.720 65.320 188.320 ;
    END
  END Tile_X0Y1_FrameData_O[24]
  PIN Tile_X0Y1_FrameData_O[25]
    DIRECTION OUTPUT ;
    USE SIGNAL ;
    ANTENNADIFFAREA 0.702900 ;
    PORT
      LAYER met3 ;
        RECT 64.720 189.080 65.320 189.680 ;
    END
  END Tile_X0Y1_FrameData_O[25]
  PIN Tile_X0Y1_FrameData_O[26]
    DIRECTION OUTPUT ;
    USE SIGNAL ;
    ANTENNADIFFAREA 0.702900 ;
    PORT
      LAYER met3 ;
        RECT 64.720 190.440 65.320 191.040 ;
    END
  END Tile_X0Y1_FrameData_O[26]
  PIN Tile_X0Y1_FrameData_O[27]
    DIRECTION OUTPUT ;
    USE SIGNAL ;
    ANTENNADIFFAREA 0.702900 ;
    PORT
      LAYER met3 ;
        RECT 64.720 191.800 65.320 192.400 ;
    END
  END Tile_X0Y1_FrameData_O[27]
  PIN Tile_X0Y1_FrameData_O[28]
    DIRECTION OUTPUT ;
    USE SIGNAL ;
    ANTENNADIFFAREA 0.702900 ;
    PORT
      LAYER met3 ;
        RECT 64.720 193.160 65.320 193.760 ;
    END
  END Tile_X0Y1_FrameData_O[28]
  PIN Tile_X0Y1_FrameData_O[29]
    DIRECTION OUTPUT ;
    USE SIGNAL ;
    ANTENNADIFFAREA 0.702900 ;
    PORT
      LAYER met3 ;
        RECT 64.720 194.520 65.320 195.120 ;
    END
  END Tile_X0Y1_FrameData_O[29]
  PIN Tile_X0Y1_FrameData_O[2]
    DIRECTION OUTPUT ;
    USE SIGNAL ;
    ANTENNADIFFAREA 0.702900 ;
    PORT
      LAYER met3 ;
        RECT 64.720 157.800 65.320 158.400 ;
    END
  END Tile_X0Y1_FrameData_O[2]
  PIN Tile_X0Y1_FrameData_O[30]
    DIRECTION OUTPUT ;
    USE SIGNAL ;
    ANTENNADIFFAREA 0.702900 ;
    PORT
      LAYER met3 ;
        RECT 64.720 195.880 65.320 196.480 ;
    END
  END Tile_X0Y1_FrameData_O[30]
  PIN Tile_X0Y1_FrameData_O[31]
    DIRECTION OUTPUT ;
    USE SIGNAL ;
    ANTENNADIFFAREA 0.702900 ;
    PORT
      LAYER met3 ;
        RECT 64.720 197.240 65.320 197.840 ;
    END
  END Tile_X0Y1_FrameData_O[31]
  PIN Tile_X0Y1_FrameData_O[3]
    DIRECTION OUTPUT ;
    USE SIGNAL ;
    ANTENNADIFFAREA 0.702900 ;
    PORT
      LAYER met3 ;
        RECT 64.720 159.160 65.320 159.760 ;
    END
  END Tile_X0Y1_FrameData_O[3]
  PIN Tile_X0Y1_FrameData_O[4]
    DIRECTION OUTPUT ;
    USE SIGNAL ;
    ANTENNADIFFAREA 0.702900 ;
    PORT
      LAYER met3 ;
        RECT 64.720 160.520 65.320 161.120 ;
    END
  END Tile_X0Y1_FrameData_O[4]
  PIN Tile_X0Y1_FrameData_O[5]
    DIRECTION OUTPUT ;
    USE SIGNAL ;
    ANTENNADIFFAREA 0.702900 ;
    PORT
      LAYER met3 ;
        RECT 64.720 161.880 65.320 162.480 ;
    END
  END Tile_X0Y1_FrameData_O[5]
  PIN Tile_X0Y1_FrameData_O[6]
    DIRECTION OUTPUT ;
    USE SIGNAL ;
    ANTENNADIFFAREA 0.702900 ;
    PORT
      LAYER met3 ;
        RECT 64.720 163.240 65.320 163.840 ;
    END
  END Tile_X0Y1_FrameData_O[6]
  PIN Tile_X0Y1_FrameData_O[7]
    DIRECTION OUTPUT ;
    USE SIGNAL ;
    ANTENNADIFFAREA 0.702900 ;
    PORT
      LAYER met3 ;
        RECT 64.720 164.600 65.320 165.200 ;
    END
  END Tile_X0Y1_FrameData_O[7]
  PIN Tile_X0Y1_FrameData_O[8]
    DIRECTION OUTPUT ;
    USE SIGNAL ;
    ANTENNADIFFAREA 0.702900 ;
    PORT
      LAYER met3 ;
        RECT 64.720 165.960 65.320 166.560 ;
    END
  END Tile_X0Y1_FrameData_O[8]
  PIN Tile_X0Y1_FrameData_O[9]
    DIRECTION OUTPUT ;
    USE SIGNAL ;
    ANTENNADIFFAREA 0.702900 ;
    PORT
      LAYER met3 ;
        RECT 64.720 167.320 65.320 167.920 ;
    END
  END Tile_X0Y1_FrameData_O[9]
  PIN Tile_X0Y1_FrameStrobe[0]
    DIRECTION INPUT ;
    USE SIGNAL ;
    ANTENNAGATEAREA 10.335000 ;
    PORT
      LAYER met2 ;
        RECT 19.870 0.000 20.150 0.280 ;
    END
  END Tile_X0Y1_FrameStrobe[0]
  PIN Tile_X0Y1_FrameStrobe[10]
    DIRECTION INPUT ;
    USE SIGNAL ;
    ANTENNAGATEAREA 0.593700 ;
    ANTENNADIFFAREA 0.434700 ;
    PORT
      LAYER met2 ;
        RECT 42.870 0.000 43.150 0.280 ;
    END
  END Tile_X0Y1_FrameStrobe[10]
  PIN Tile_X0Y1_FrameStrobe[11]
    DIRECTION INPUT ;
    USE SIGNAL ;
    ANTENNAGATEAREA 2.332500 ;
    ANTENNADIFFAREA 2.173500 ;
    PORT
      LAYER met2 ;
        RECT 45.170 0.000 45.450 0.280 ;
    END
  END Tile_X0Y1_FrameStrobe[11]
  PIN Tile_X0Y1_FrameStrobe[12]
    DIRECTION INPUT ;
    USE SIGNAL ;
    ANTENNAGATEAREA 0.593700 ;
    ANTENNADIFFAREA 0.434700 ;
    PORT
      LAYER met2 ;
        RECT 47.470 0.000 47.750 0.280 ;
    END
  END Tile_X0Y1_FrameStrobe[12]
  PIN Tile_X0Y1_FrameStrobe[13]
    DIRECTION INPUT ;
    USE SIGNAL ;
    ANTENNAGATEAREA 4.071300 ;
    ANTENNADIFFAREA 3.912300 ;
    PORT
      LAYER met2 ;
        RECT 49.770 0.000 50.050 0.280 ;
    END
  END Tile_X0Y1_FrameStrobe[13]
  PIN Tile_X0Y1_FrameStrobe[14]
    DIRECTION INPUT ;
    USE SIGNAL ;
    ANTENNAGATEAREA 0.593700 ;
    ANTENNADIFFAREA 0.434700 ;
    PORT
      LAYER met2 ;
        RECT 52.070 0.000 52.350 0.280 ;
    END
  END Tile_X0Y1_FrameStrobe[14]
  PIN Tile_X0Y1_FrameStrobe[15]
    DIRECTION INPUT ;
    USE SIGNAL ;
    ANTENNAGATEAREA 1.028400 ;
    ANTENNADIFFAREA 0.869400 ;
    PORT
      LAYER met2 ;
        RECT 54.370 0.000 54.650 0.280 ;
    END
  END Tile_X0Y1_FrameStrobe[15]
  PIN Tile_X0Y1_FrameStrobe[16]
    DIRECTION INPUT ;
    USE SIGNAL ;
    ANTENNAGATEAREA 4.506000 ;
    ANTENNADIFFAREA 4.347000 ;
    PORT
      LAYER met2 ;
        RECT 56.670 0.000 56.950 0.280 ;
    END
  END Tile_X0Y1_FrameStrobe[16]
  PIN Tile_X0Y1_FrameStrobe[17]
    DIRECTION INPUT ;
    USE SIGNAL ;
    ANTENNAGATEAREA 1.028400 ;
    ANTENNADIFFAREA 0.869400 ;
    PORT
      LAYER met2 ;
        RECT 58.970 0.000 59.250 0.280 ;
    END
  END Tile_X0Y1_FrameStrobe[17]
  PIN Tile_X0Y1_FrameStrobe[18]
    DIRECTION INPUT ;
    USE SIGNAL ;
    ANTENNAGATEAREA 0.593700 ;
    ANTENNADIFFAREA 0.434700 ;
    PORT
      LAYER met2 ;
        RECT 61.270 0.000 61.550 0.280 ;
    END
  END Tile_X0Y1_FrameStrobe[18]
  PIN Tile_X0Y1_FrameStrobe[19]
    DIRECTION INPUT ;
    USE SIGNAL ;
    ANTENNAGATEAREA 3.636600 ;
    ANTENNADIFFAREA 3.477600 ;
    PORT
      LAYER met2 ;
        RECT 63.570 0.000 63.850 0.280 ;
    END
  END Tile_X0Y1_FrameStrobe[19]
  PIN Tile_X0Y1_FrameStrobe[1]
    DIRECTION INPUT ;
    USE SIGNAL ;
    ANTENNAGATEAREA 10.335000 ;
    PORT
      LAYER met2 ;
        RECT 22.170 0.000 22.450 0.280 ;
    END
  END Tile_X0Y1_FrameStrobe[1]
  PIN Tile_X0Y1_FrameStrobe[2]
    DIRECTION INPUT ;
    USE SIGNAL ;
    ANTENNAGATEAREA 10.335000 ;
    PORT
      LAYER met2 ;
        RECT 24.470 0.000 24.750 0.280 ;
    END
  END Tile_X0Y1_FrameStrobe[2]
  PIN Tile_X0Y1_FrameStrobe[3]
    DIRECTION INPUT ;
    USE SIGNAL ;
    ANTENNAGATEAREA 9.698999 ;
    PORT
      LAYER met2 ;
        RECT 26.770 0.000 27.050 0.280 ;
    END
  END Tile_X0Y1_FrameStrobe[3]
  PIN Tile_X0Y1_FrameStrobe[4]
    DIRECTION INPUT ;
    USE SIGNAL ;
    ANTENNAGATEAREA 2.226000 ;
    PORT
      LAYER met2 ;
        RECT 29.070 0.000 29.350 0.280 ;
    END
  END Tile_X0Y1_FrameStrobe[4]
  PIN Tile_X0Y1_FrameStrobe[5]
    DIRECTION INPUT ;
    USE SIGNAL ;
    ANTENNAGATEAREA 0.593700 ;
    ANTENNADIFFAREA 0.434700 ;
    PORT
      LAYER met2 ;
        RECT 31.370 0.000 31.650 0.280 ;
    END
  END Tile_X0Y1_FrameStrobe[5]
  PIN Tile_X0Y1_FrameStrobe[6]
    DIRECTION INPUT ;
    USE SIGNAL ;
    ANTENNAGATEAREA 2.767200 ;
    ANTENNADIFFAREA 2.608200 ;
    PORT
      LAYER met2 ;
        RECT 33.670 0.000 33.950 0.280 ;
    END
  END Tile_X0Y1_FrameStrobe[6]
  PIN Tile_X0Y1_FrameStrobe[7]
    DIRECTION INPUT ;
    USE SIGNAL ;
    ANTENNAGATEAREA 0.593700 ;
    ANTENNADIFFAREA 0.434700 ;
    PORT
      LAYER met2 ;
        RECT 35.970 0.000 36.250 0.280 ;
    END
  END Tile_X0Y1_FrameStrobe[7]
  PIN Tile_X0Y1_FrameStrobe[8]
    DIRECTION INPUT ;
    USE SIGNAL ;
    ANTENNAGATEAREA 2.332500 ;
    ANTENNADIFFAREA 2.173500 ;
    PORT
      LAYER met2 ;
        RECT 38.270 0.000 38.550 0.280 ;
    END
  END Tile_X0Y1_FrameStrobe[8]
  PIN Tile_X0Y1_FrameStrobe[9]
    DIRECTION INPUT ;
    USE SIGNAL ;
    ANTENNAGATEAREA 2.767200 ;
    ANTENNADIFFAREA 2.608200 ;
    PORT
      LAYER met2 ;
        RECT 40.570 0.000 40.850 0.280 ;
    END
  END Tile_X0Y1_FrameStrobe[9]
  PIN Tile_X0Y1_N_GBUF_END[0]
    DIRECTION INPUT ;
    USE SIGNAL ;
    ANTENNAGATEAREA 0.852000 ;
    PORT
      LAYER met2 ;
        RECT 1.470 0.000 1.750 0.280 ;
    END
  END Tile_X0Y1_N_GBUF_END[0]
  PIN Tile_X0Y1_N_GBUF_END[1]
    DIRECTION INPUT ;
    USE SIGNAL ;
    ANTENNAGATEAREA 1.781100 ;
    ANTENNADIFFAREA 1.304100 ;
    PORT
      LAYER met2 ;
        RECT 3.770 0.000 4.050 0.280 ;
    END
  END Tile_X0Y1_N_GBUF_END[1]
  PIN Tile_X0Y1_N_GBUF_END[2]
    DIRECTION INPUT ;
    USE SIGNAL ;
    ANTENNAGATEAREA 1.781100 ;
    ANTENNADIFFAREA 1.304100 ;
    PORT
      LAYER met2 ;
        RECT 6.070 0.000 6.350 0.280 ;
    END
  END Tile_X0Y1_N_GBUF_END[2]
  PIN Tile_X0Y1_N_GBUF_END[3]
    DIRECTION INPUT ;
    USE SIGNAL ;
    ANTENNAGATEAREA 1.781100 ;
    ANTENNADIFFAREA 1.304100 ;
    PORT
      LAYER met2 ;
        RECT 8.370 0.000 8.650 0.280 ;
    END
  END Tile_X0Y1_N_GBUF_END[3]
  PIN Tile_X0Y1_S_GBUF_FEED_BEG[0]
    DIRECTION OUTPUT ;
    USE SIGNAL ;
    ANTENNADIFFAREA 0.702900 ;
    PORT
      LAYER met2 ;
        RECT 10.670 0.000 10.950 0.280 ;
    END
  END Tile_X0Y1_S_GBUF_FEED_BEG[0]
  PIN Tile_X0Y1_S_GBUF_FEED_BEG[1]
    DIRECTION OUTPUT ;
    USE SIGNAL ;
    ANTENNADIFFAREA 0.702900 ;
    PORT
      LAYER met2 ;
        RECT 12.970 0.000 13.250 0.280 ;
    END
  END Tile_X0Y1_S_GBUF_FEED_BEG[1]
  PIN Tile_X0Y1_S_GBUF_FEED_BEG[2]
    DIRECTION OUTPUT ;
    USE SIGNAL ;
    ANTENNADIFFAREA 0.702900 ;
    PORT
      LAYER met2 ;
        RECT 15.270 0.000 15.550 0.280 ;
    END
  END Tile_X0Y1_S_GBUF_FEED_BEG[2]
  PIN Tile_X0Y1_S_GBUF_FEED_BEG[3]
    DIRECTION OUTPUT ;
    USE SIGNAL ;
    ANTENNADIFFAREA 0.702900 ;
    PORT
      LAYER met2 ;
        RECT 17.570 0.000 17.850 0.280 ;
    END
  END Tile_X0Y1_S_GBUF_FEED_BEG[3]
  PIN Tile_X0Y1_W1END[0]
    DIRECTION INPUT ;
    USE SIGNAL ;
    ANTENNAGATEAREA 1.014000 ;
    PORT
      LAYER met3 ;
        RECT 64.720 24.520 65.320 25.120 ;
    END
  END Tile_X0Y1_W1END[0]
  PIN Tile_X0Y1_W1END[1]
    DIRECTION INPUT ;
    USE SIGNAL ;
    ANTENNAGATEAREA 0.729000 ;
    PORT
      LAYER met3 ;
        RECT 64.720 25.880 65.320 26.480 ;
    END
  END Tile_X0Y1_W1END[1]
  PIN Tile_X0Y1_W1END[2]
    DIRECTION INPUT ;
    USE SIGNAL ;
    ANTENNAGATEAREA 0.729000 ;
    PORT
      LAYER met3 ;
        RECT 64.720 27.240 65.320 27.840 ;
    END
  END Tile_X0Y1_W1END[2]
  PIN Tile_X0Y1_W1END[3]
    DIRECTION INPUT ;
    USE SIGNAL ;
    ANTENNAGATEAREA 0.888000 ;
    PORT
      LAYER met3 ;
        RECT 64.720 28.600 65.320 29.200 ;
    END
  END Tile_X0Y1_W1END[3]
  PIN Tile_X0Y1_W2END[0]
    DIRECTION INPUT ;
    USE SIGNAL ;
    ANTENNAGATEAREA 1.308000 ;
    PORT
      LAYER met3 ;
        RECT 64.720 40.840 65.320 41.440 ;
    END
  END Tile_X0Y1_W2END[0]
  PIN Tile_X0Y1_W2END[1]
    DIRECTION INPUT ;
    USE SIGNAL ;
    ANTENNAGATEAREA 1.308000 ;
    PORT
      LAYER met3 ;
        RECT 64.720 42.200 65.320 42.800 ;
    END
  END Tile_X0Y1_W2END[1]
  PIN Tile_X0Y1_W2END[2]
    DIRECTION INPUT ;
    USE SIGNAL ;
    ANTENNAGATEAREA 1.434000 ;
    PORT
      LAYER met3 ;
        RECT 64.720 43.560 65.320 44.160 ;
    END
  END Tile_X0Y1_W2END[2]
  PIN Tile_X0Y1_W2END[3]
    DIRECTION INPUT ;
    USE SIGNAL ;
    ANTENNAGATEAREA 1.308000 ;
    PORT
      LAYER met3 ;
        RECT 64.720 44.920 65.320 45.520 ;
    END
  END Tile_X0Y1_W2END[3]
  PIN Tile_X0Y1_W2END[4]
    DIRECTION INPUT ;
    USE SIGNAL ;
    ANTENNAGATEAREA 1.555500 ;
    PORT
      LAYER met3 ;
        RECT 64.720 46.280 65.320 46.880 ;
    END
  END Tile_X0Y1_W2END[4]
  PIN Tile_X0Y1_W2END[5]
    DIRECTION INPUT ;
    USE SIGNAL ;
    ANTENNAGATEAREA 1.681500 ;
    PORT
      LAYER met3 ;
        RECT 64.720 47.640 65.320 48.240 ;
    END
  END Tile_X0Y1_W2END[5]
  PIN Tile_X0Y1_W2END[6]
    DIRECTION INPUT ;
    USE SIGNAL ;
    ANTENNAGATEAREA 1.060500 ;
    PORT
      LAYER met3 ;
        RECT 64.720 49.000 65.320 49.600 ;
    END
  END Tile_X0Y1_W2END[6]
  PIN Tile_X0Y1_W2END[7]
    DIRECTION INPUT ;
    USE SIGNAL ;
    ANTENNAGATEAREA 1.060500 ;
    PORT
      LAYER met3 ;
        RECT 64.720 50.360 65.320 50.960 ;
    END
  END Tile_X0Y1_W2END[7]
  PIN Tile_X0Y1_W2MID[0]
    DIRECTION INPUT ;
    USE SIGNAL ;
    ANTENNAGATEAREA 0.560700 ;
    ANTENNADIFFAREA 0.434700 ;
    PORT
      LAYER met3 ;
        RECT 64.720 29.960 65.320 30.560 ;
    END
  END Tile_X0Y1_W2MID[0]
  PIN Tile_X0Y1_W2MID[1]
    DIRECTION INPUT ;
    USE SIGNAL ;
    ANTENNAGATEAREA 0.126000 ;
    PORT
      LAYER met3 ;
        RECT 64.720 31.320 65.320 31.920 ;
    END
  END Tile_X0Y1_W2MID[1]
  PIN Tile_X0Y1_W2MID[2]
    DIRECTION INPUT ;
    USE SIGNAL ;
    ANTENNAGATEAREA 1.715100 ;
    ANTENNADIFFAREA 1.304100 ;
    PORT
      LAYER met3 ;
        RECT 64.720 32.680 65.320 33.280 ;
    END
  END Tile_X0Y1_W2MID[2]
  PIN Tile_X0Y1_W2MID[3]
    DIRECTION INPUT ;
    USE SIGNAL ;
    ANTENNAGATEAREA 0.560700 ;
    ANTENNADIFFAREA 0.434700 ;
    PORT
      LAYER met3 ;
        RECT 64.720 34.040 65.320 34.640 ;
    END
  END Tile_X0Y1_W2MID[3]
  PIN Tile_X0Y1_W2MID[4]
    DIRECTION INPUT ;
    USE SIGNAL ;
    ANTENNAGATEAREA 0.560700 ;
    ANTENNADIFFAREA 0.434700 ;
    PORT
      LAYER met3 ;
        RECT 64.720 35.400 65.320 36.000 ;
    END
  END Tile_X0Y1_W2MID[4]
  PIN Tile_X0Y1_W2MID[5]
    DIRECTION INPUT ;
    USE SIGNAL ;
    ANTENNAGATEAREA 0.126000 ;
    PORT
      LAYER met3 ;
        RECT 64.720 36.760 65.320 37.360 ;
    END
  END Tile_X0Y1_W2MID[5]
  PIN Tile_X0Y1_W2MID[6]
    DIRECTION INPUT ;
    USE SIGNAL ;
    ANTENNAGATEAREA 1.214700 ;
    ANTENNADIFFAREA 0.434700 ;
    PORT
      LAYER met3 ;
        RECT 64.720 38.120 65.320 38.720 ;
    END
  END Tile_X0Y1_W2MID[6]
  PIN Tile_X0Y1_W2MID[7]
    DIRECTION INPUT ;
    USE SIGNAL ;
    ANTENNAGATEAREA 0.560700 ;
    ANTENNADIFFAREA 0.434700 ;
    PORT
      LAYER met3 ;
        RECT 64.720 39.480 65.320 40.080 ;
    END
  END Tile_X0Y1_W2MID[7]
  PIN Tile_X0Y1_W6END[0]
    DIRECTION INPUT ;
    USE SIGNAL ;
    ANTENNAGATEAREA 1.532400 ;
    ANTENNADIFFAREA 0.869400 ;
    PORT
      LAYER met3 ;
        RECT 64.720 73.480 65.320 74.080 ;
    END
  END Tile_X0Y1_W6END[0]
  PIN Tile_X0Y1_W6END[10]
    DIRECTION INPUT ;
    USE SIGNAL ;
    PORT
      LAYER met3 ;
        RECT 64.720 87.080 65.320 87.680 ;
    END
  END Tile_X0Y1_W6END[10]
  PIN Tile_X0Y1_W6END[11]
    DIRECTION INPUT ;
    USE SIGNAL ;
    ANTENNAGATEAREA 0.719700 ;
    ANTENNADIFFAREA 0.434700 ;
    PORT
      LAYER met3 ;
        RECT 64.720 88.440 65.320 89.040 ;
    END
  END Tile_X0Y1_W6END[11]
  PIN Tile_X0Y1_W6END[1]
    DIRECTION INPUT ;
    USE SIGNAL ;
    ANTENNAGATEAREA 0.378000 ;
    PORT
      LAYER met3 ;
        RECT 64.720 74.840 65.320 75.440 ;
    END
  END Tile_X0Y1_W6END[1]
  PIN Tile_X0Y1_W6END[2]
    DIRECTION INPUT ;
    USE SIGNAL ;
    ANTENNAGATEAREA 1.433700 ;
    ANTENNADIFFAREA 0.434700 ;
    PORT
      LAYER met3 ;
        RECT 64.720 76.200 65.320 76.800 ;
    END
  END Tile_X0Y1_W6END[2]
  PIN Tile_X0Y1_W6END[3]
    DIRECTION INPUT ;
    USE SIGNAL ;
    ANTENNAGATEAREA 0.873000 ;
    PORT
      LAYER met3 ;
        RECT 64.720 77.560 65.320 78.160 ;
    END
  END Tile_X0Y1_W6END[3]
  PIN Tile_X0Y1_W6END[4]
    DIRECTION INPUT ;
    USE SIGNAL ;
    ANTENNAGATEAREA 0.537000 ;
    PORT
      LAYER met3 ;
        RECT 64.720 78.920 65.320 79.520 ;
    END
  END Tile_X0Y1_W6END[4]
  PIN Tile_X0Y1_W6END[5]
    DIRECTION INPUT ;
    USE SIGNAL ;
    ANTENNAGATEAREA 0.252000 ;
    PORT
      LAYER met3 ;
        RECT 64.720 80.280 65.320 80.880 ;
    END
  END Tile_X0Y1_W6END[5]
  PIN Tile_X0Y1_W6END[6]
    DIRECTION INPUT ;
    USE SIGNAL ;
    ANTENNAGATEAREA 1.682100 ;
    ANTENNADIFFAREA 1.304100 ;
    PORT
      LAYER met3 ;
        RECT 64.720 81.640 65.320 82.240 ;
    END
  END Tile_X0Y1_W6END[6]
  PIN Tile_X0Y1_W6END[7]
    DIRECTION INPUT ;
    USE SIGNAL ;
    ANTENNAGATEAREA 0.378000 ;
    PORT
      LAYER met3 ;
        RECT 64.720 83.000 65.320 83.600 ;
    END
  END Tile_X0Y1_W6END[7]
  PIN Tile_X0Y1_W6END[8]
    DIRECTION INPUT ;
    USE SIGNAL ;
    ANTENNAGATEAREA 0.411000 ;
    PORT
      LAYER met3 ;
        RECT 64.720 84.360 65.320 84.960 ;
    END
  END Tile_X0Y1_W6END[8]
  PIN Tile_X0Y1_W6END[9]
    DIRECTION INPUT ;
    USE SIGNAL ;
    ANTENNAGATEAREA 0.126000 ;
    PORT
      LAYER met3 ;
        RECT 64.720 85.720 65.320 86.320 ;
    END
  END Tile_X0Y1_W6END[9]
  PIN Tile_X0Y1_WW4END[0]
    DIRECTION INPUT ;
    USE SIGNAL ;
    ANTENNAGATEAREA 0.663000 ;
    PORT
      LAYER met3 ;
        RECT 64.720 51.720 65.320 52.320 ;
    END
  END Tile_X0Y1_WW4END[0]
  PIN Tile_X0Y1_WW4END[10]
    DIRECTION INPUT ;
    USE SIGNAL ;
    ANTENNAGATEAREA 0.906000 ;
    PORT
      LAYER met3 ;
        RECT 64.720 65.320 65.320 65.920 ;
    END
  END Tile_X0Y1_WW4END[10]
  PIN Tile_X0Y1_WW4END[11]
    DIRECTION INPUT ;
    USE SIGNAL ;
    ANTENNAGATEAREA 0.906000 ;
    PORT
      LAYER met3 ;
        RECT 64.720 66.680 65.320 67.280 ;
    END
  END Tile_X0Y1_WW4END[11]
  PIN Tile_X0Y1_WW4END[12]
    DIRECTION INPUT ;
    USE SIGNAL ;
    ANTENNAGATEAREA 0.906000 ;
    PORT
      LAYER met3 ;
        RECT 64.720 68.040 65.320 68.640 ;
    END
  END Tile_X0Y1_WW4END[12]
  PIN Tile_X0Y1_WW4END[13]
    DIRECTION INPUT ;
    USE SIGNAL ;
    ANTENNAGATEAREA 0.906000 ;
    PORT
      LAYER met3 ;
        RECT 64.720 69.400 65.320 70.000 ;
    END
  END Tile_X0Y1_WW4END[13]
  PIN Tile_X0Y1_WW4END[14]
    DIRECTION INPUT ;
    USE SIGNAL ;
    ANTENNAGATEAREA 0.906000 ;
    PORT
      LAYER met3 ;
        RECT 64.720 70.760 65.320 71.360 ;
    END
  END Tile_X0Y1_WW4END[14]
  PIN Tile_X0Y1_WW4END[15]
    DIRECTION INPUT ;
    USE SIGNAL ;
    ANTENNAGATEAREA 0.906000 ;
    PORT
      LAYER met3 ;
        RECT 64.720 72.120 65.320 72.720 ;
    END
  END Tile_X0Y1_WW4END[15]
  PIN Tile_X0Y1_WW4END[1]
    DIRECTION INPUT ;
    USE SIGNAL ;
    ANTENNAGATEAREA 1.097700 ;
    ANTENNADIFFAREA 0.434700 ;
    PORT
      LAYER met3 ;
        RECT 64.720 53.080 65.320 53.680 ;
    END
  END Tile_X0Y1_WW4END[1]
  PIN Tile_X0Y1_WW4END[2]
    DIRECTION INPUT ;
    USE SIGNAL ;
    ANTENNAGATEAREA 0.663000 ;
    PORT
      LAYER met3 ;
        RECT 64.720 54.440 65.320 55.040 ;
    END
  END Tile_X0Y1_WW4END[2]
  PIN Tile_X0Y1_WW4END[3]
    DIRECTION INPUT ;
    USE SIGNAL ;
    ANTENNAGATEAREA 0.663000 ;
    PORT
      LAYER met3 ;
        RECT 64.720 55.800 65.320 56.400 ;
    END
  END Tile_X0Y1_WW4END[3]
  PIN Tile_X0Y1_WW4END[4]
    DIRECTION INPUT ;
    USE SIGNAL ;
    ANTENNAGATEAREA 0.537000 ;
    PORT
      LAYER met3 ;
        RECT 64.720 57.160 65.320 57.760 ;
    END
  END Tile_X0Y1_WW4END[4]
  PIN Tile_X0Y1_WW4END[5]
    DIRECTION INPUT ;
    USE SIGNAL ;
    ANTENNAGATEAREA 1.466700 ;
    ANTENNADIFFAREA 0.434700 ;
    PORT
      LAYER met3 ;
        RECT 64.720 58.520 65.320 59.120 ;
    END
  END Tile_X0Y1_WW4END[5]
  PIN Tile_X0Y1_WW4END[6]
    DIRECTION INPUT ;
    USE SIGNAL ;
    ANTENNAGATEAREA 0.537000 ;
    PORT
      LAYER met3 ;
        RECT 64.720 59.880 65.320 60.480 ;
    END
  END Tile_X0Y1_WW4END[6]
  PIN Tile_X0Y1_WW4END[7]
    DIRECTION INPUT ;
    USE SIGNAL ;
    ANTENNAGATEAREA 2.275800 ;
    ANTENNADIFFAREA 1.738800 ;
    PORT
      LAYER met3 ;
        RECT 64.720 61.240 65.320 61.840 ;
    END
  END Tile_X0Y1_WW4END[7]
  PIN Tile_X0Y1_WW4END[8]
    DIRECTION INPUT ;
    USE SIGNAL ;
    ANTENNAGATEAREA 0.906000 ;
    PORT
      LAYER met3 ;
        RECT 64.720 62.600 65.320 63.200 ;
    END
  END Tile_X0Y1_WW4END[8]
  PIN Tile_X0Y1_WW4END[9]
    DIRECTION INPUT ;
    USE SIGNAL ;
    ANTENNAGATEAREA 0.906000 ;
    PORT
      LAYER met3 ;
        RECT 64.720 63.960 65.320 64.560 ;
    END
  END Tile_X0Y1_WW4END[9]
  PIN UIO_IN_TT_PROJECT0
    DIRECTION OUTPUT ;
    USE SIGNAL ;
    ANTENNADIFFAREA 0.702900 ;
    PORT
      LAYER met3 ;
        RECT 0.000 103.400 0.600 104.000 ;
    END
  END UIO_IN_TT_PROJECT0
  PIN UIO_IN_TT_PROJECT1
    DIRECTION OUTPUT ;
    USE SIGNAL ;
    ANTENNADIFFAREA 0.702900 ;
    PORT
      LAYER met3 ;
        RECT 0.000 106.120 0.600 106.720 ;
    END
  END UIO_IN_TT_PROJECT1
  PIN UIO_IN_TT_PROJECT2
    DIRECTION OUTPUT ;
    USE SIGNAL ;
    ANTENNADIFFAREA 0.702900 ;
    PORT
      LAYER met3 ;
        RECT 0.000 108.840 0.600 109.440 ;
    END
  END UIO_IN_TT_PROJECT2
  PIN UIO_IN_TT_PROJECT3
    DIRECTION OUTPUT ;
    USE SIGNAL ;
    ANTENNADIFFAREA 0.702900 ;
    PORT
      LAYER met3 ;
        RECT 0.000 111.560 0.600 112.160 ;
    END
  END UIO_IN_TT_PROJECT3
  PIN UIO_IN_TT_PROJECT4
    DIRECTION OUTPUT ;
    USE SIGNAL ;
    ANTENNADIFFAREA 0.702900 ;
    PORT
      LAYER met3 ;
        RECT 0.000 114.280 0.600 114.880 ;
    END
  END UIO_IN_TT_PROJECT4
  PIN UIO_IN_TT_PROJECT5
    DIRECTION OUTPUT ;
    USE SIGNAL ;
    ANTENNADIFFAREA 0.702900 ;
    PORT
      LAYER met3 ;
        RECT 0.000 117.000 0.600 117.600 ;
    END
  END UIO_IN_TT_PROJECT5
  PIN UIO_IN_TT_PROJECT6
    DIRECTION OUTPUT ;
    USE SIGNAL ;
    ANTENNADIFFAREA 0.702900 ;
    PORT
      LAYER met3 ;
        RECT 0.000 119.720 0.600 120.320 ;
    END
  END UIO_IN_TT_PROJECT6
  PIN UIO_IN_TT_PROJECT7
    DIRECTION OUTPUT ;
    USE SIGNAL ;
    ANTENNADIFFAREA 0.702900 ;
    PORT
      LAYER met3 ;
        RECT 0.000 122.440 0.600 123.040 ;
    END
  END UIO_IN_TT_PROJECT7
  PIN UIO_OE_TT_PROJECT0
    DIRECTION INPUT ;
    USE SIGNAL ;
    ANTENNAGATEAREA 1.557000 ;
    PORT
      LAYER met3 ;
        RECT 0.000 59.880 0.600 60.480 ;
    END
  END UIO_OE_TT_PROJECT0
  PIN UIO_OE_TT_PROJECT1
    DIRECTION INPUT ;
    USE SIGNAL ;
    ANTENNAGATEAREA 1.991700 ;
    ANTENNADIFFAREA 0.434700 ;
    PORT
      LAYER met3 ;
        RECT 0.000 62.600 0.600 63.200 ;
    END
  END UIO_OE_TT_PROJECT1
  PIN UIO_OE_TT_PROJECT2
    DIRECTION INPUT ;
    USE SIGNAL ;
    ANTENNAGATEAREA 2.861100 ;
    ANTENNADIFFAREA 1.304100 ;
    PORT
      LAYER met3 ;
        RECT 0.000 65.320 0.600 65.920 ;
    END
  END UIO_OE_TT_PROJECT2
  PIN UIO_OE_TT_PROJECT3
    DIRECTION INPUT ;
    USE SIGNAL ;
    ANTENNAGATEAREA 1.557000 ;
    PORT
      LAYER met3 ;
        RECT 0.000 68.040 0.600 68.640 ;
    END
  END UIO_OE_TT_PROJECT3
  PIN UIO_OE_TT_PROJECT4
    DIRECTION INPUT ;
    USE SIGNAL ;
    ANTENNAGATEAREA 1.991700 ;
    ANTENNADIFFAREA 0.434700 ;
    PORT
      LAYER met3 ;
        RECT 0.000 70.760 0.600 71.360 ;
    END
  END UIO_OE_TT_PROJECT4
  PIN UIO_OE_TT_PROJECT5
    DIRECTION INPUT ;
    USE SIGNAL ;
    ANTENNAGATEAREA 1.991700 ;
    ANTENNADIFFAREA 0.434700 ;
    PORT
      LAYER met3 ;
        RECT 0.000 73.480 0.600 74.080 ;
    END
  END UIO_OE_TT_PROJECT5
  PIN UIO_OE_TT_PROJECT6
    DIRECTION INPUT ;
    USE SIGNAL ;
    ANTENNAGATEAREA 1.557000 ;
    PORT
      LAYER met3 ;
        RECT 0.000 76.200 0.600 76.800 ;
    END
  END UIO_OE_TT_PROJECT6
  PIN UIO_OE_TT_PROJECT7
    DIRECTION INPUT ;
    USE SIGNAL ;
    ANTENNAGATEAREA 1.557000 ;
    PORT
      LAYER met3 ;
        RECT 0.000 78.920 0.600 79.520 ;
    END
  END UIO_OE_TT_PROJECT7
  PIN UIO_OUT_TT_PROJECT0
    DIRECTION INPUT ;
    USE SIGNAL ;
    ANTENNAGATEAREA 2.160000 ;
    PORT
      LAYER met3 ;
        RECT 0.000 38.120 0.600 38.720 ;
    END
  END UIO_OUT_TT_PROJECT0
  PIN UIO_OUT_TT_PROJECT1
    DIRECTION INPUT ;
    USE SIGNAL ;
    ANTENNAGATEAREA 2.160000 ;
    PORT
      LAYER met3 ;
        RECT 0.000 40.840 0.600 41.440 ;
    END
  END UIO_OUT_TT_PROJECT1
  PIN UIO_OUT_TT_PROJECT2
    DIRECTION INPUT ;
    USE SIGNAL ;
    ANTENNAGATEAREA 2.160000 ;
    PORT
      LAYER met3 ;
        RECT 0.000 43.560 0.600 44.160 ;
    END
  END UIO_OUT_TT_PROJECT2
  PIN UIO_OUT_TT_PROJECT3
    DIRECTION INPUT ;
    USE SIGNAL ;
    ANTENNAGATEAREA 2.594700 ;
    ANTENNADIFFAREA 0.434700 ;
    PORT
      LAYER met3 ;
        RECT 0.000 46.280 0.600 46.880 ;
    END
  END UIO_OUT_TT_PROJECT3
  PIN UIO_OUT_TT_PROJECT4
    DIRECTION INPUT ;
    USE SIGNAL ;
    ANTENNAGATEAREA 2.160000 ;
    PORT
      LAYER met3 ;
        RECT 0.000 49.000 0.600 49.600 ;
    END
  END UIO_OUT_TT_PROJECT4
  PIN UIO_OUT_TT_PROJECT5
    DIRECTION INPUT ;
    USE SIGNAL ;
    ANTENNAGATEAREA 2.160000 ;
    PORT
      LAYER met3 ;
        RECT 0.000 51.720 0.600 52.320 ;
    END
  END UIO_OUT_TT_PROJECT5
  PIN UIO_OUT_TT_PROJECT6
    DIRECTION INPUT ;
    USE SIGNAL ;
    ANTENNAGATEAREA 2.160000 ;
    PORT
      LAYER met3 ;
        RECT 0.000 54.440 0.600 55.040 ;
    END
  END UIO_OUT_TT_PROJECT6
  PIN UIO_OUT_TT_PROJECT7
    DIRECTION INPUT ;
    USE SIGNAL ;
    ANTENNAGATEAREA 2.160000 ;
    PORT
      LAYER met3 ;
        RECT 0.000 57.160 0.600 57.760 ;
    END
  END UIO_OUT_TT_PROJECT7
  PIN UI_IN_TT_PROJECT0
    DIRECTION OUTPUT ;
    USE SIGNAL ;
    ANTENNADIFFAREA 0.702900 ;
    PORT
      LAYER met3 ;
        RECT 0.000 81.640 0.600 82.240 ;
    END
  END UI_IN_TT_PROJECT0
  PIN UI_IN_TT_PROJECT1
    DIRECTION OUTPUT ;
    USE SIGNAL ;
    ANTENNADIFFAREA 0.702900 ;
    PORT
      LAYER met3 ;
        RECT 0.000 84.360 0.600 84.960 ;
    END
  END UI_IN_TT_PROJECT1
  PIN UI_IN_TT_PROJECT2
    DIRECTION OUTPUT ;
    USE SIGNAL ;
    ANTENNADIFFAREA 0.702900 ;
    PORT
      LAYER met3 ;
        RECT 0.000 87.080 0.600 87.680 ;
    END
  END UI_IN_TT_PROJECT2
  PIN UI_IN_TT_PROJECT3
    DIRECTION OUTPUT ;
    USE SIGNAL ;
    ANTENNADIFFAREA 0.702900 ;
    PORT
      LAYER met3 ;
        RECT 0.000 89.800 0.600 90.400 ;
    END
  END UI_IN_TT_PROJECT3
  PIN UI_IN_TT_PROJECT4
    DIRECTION OUTPUT ;
    USE SIGNAL ;
    ANTENNADIFFAREA 0.702900 ;
    PORT
      LAYER met3 ;
        RECT 0.000 92.520 0.600 93.120 ;
    END
  END UI_IN_TT_PROJECT4
  PIN UI_IN_TT_PROJECT5
    DIRECTION OUTPUT ;
    USE SIGNAL ;
    ANTENNADIFFAREA 0.702900 ;
    PORT
      LAYER met3 ;
        RECT 0.000 95.240 0.600 95.840 ;
    END
  END UI_IN_TT_PROJECT5
  PIN UI_IN_TT_PROJECT6
    DIRECTION OUTPUT ;
    USE SIGNAL ;
    ANTENNADIFFAREA 0.702900 ;
    PORT
      LAYER met3 ;
        RECT 0.000 97.960 0.600 98.560 ;
    END
  END UI_IN_TT_PROJECT6
  PIN UI_IN_TT_PROJECT7
    DIRECTION OUTPUT ;
    USE SIGNAL ;
    ANTENNADIFFAREA 0.702900 ;
    PORT
      LAYER met3 ;
        RECT 0.000 100.680 0.600 101.280 ;
    END
  END UI_IN_TT_PROJECT7
  PIN UO_OUT_TT_PROJECT0
    DIRECTION INPUT ;
    USE SIGNAL ;
    ANTENNAGATEAREA 1.080000 ;
    PORT
      LAYER met3 ;
        RECT 0.000 16.360 0.600 16.960 ;
    END
  END UO_OUT_TT_PROJECT0
  PIN UO_OUT_TT_PROJECT1
    DIRECTION INPUT ;
    USE SIGNAL ;
    ANTENNAGATEAREA 1.080000 ;
    PORT
      LAYER met3 ;
        RECT 0.000 19.080 0.600 19.680 ;
    END
  END UO_OUT_TT_PROJECT1
  PIN UO_OUT_TT_PROJECT2
    DIRECTION INPUT ;
    USE SIGNAL ;
    ANTENNAGATEAREA 1.080000 ;
    PORT
      LAYER met3 ;
        RECT 0.000 21.800 0.600 22.400 ;
    END
  END UO_OUT_TT_PROJECT2
  PIN UO_OUT_TT_PROJECT3
    DIRECTION INPUT ;
    USE SIGNAL ;
    ANTENNAGATEAREA 1.080000 ;
    PORT
      LAYER met3 ;
        RECT 0.000 24.520 0.600 25.120 ;
    END
  END UO_OUT_TT_PROJECT3
  PIN UO_OUT_TT_PROJECT4
    DIRECTION INPUT ;
    USE SIGNAL ;
    ANTENNAGATEAREA 0.921000 ;
    PORT
      LAYER met3 ;
        RECT 0.000 27.240 0.600 27.840 ;
    END
  END UO_OUT_TT_PROJECT4
  PIN UO_OUT_TT_PROJECT5
    DIRECTION INPUT ;
    USE SIGNAL ;
    ANTENNAGATEAREA 0.921000 ;
    PORT
      LAYER met3 ;
        RECT 0.000 29.960 0.600 30.560 ;
    END
  END UO_OUT_TT_PROJECT5
  PIN UO_OUT_TT_PROJECT6
    DIRECTION INPUT ;
    USE SIGNAL ;
    ANTENNAGATEAREA 0.921000 ;
    PORT
      LAYER met3 ;
        RECT 0.000 32.680 0.600 33.280 ;
    END
  END UO_OUT_TT_PROJECT6
  PIN UO_OUT_TT_PROJECT7
    DIRECTION INPUT ;
    USE SIGNAL ;
    ANTENNAGATEAREA 0.921000 ;
    PORT
      LAYER met3 ;
        RECT 0.000 35.400 0.600 36.000 ;
    END
  END UO_OUT_TT_PROJECT7
  PIN VGND
    DIRECTION INOUT ;
    USE GROUND ;
    PORT
      LAYER met4 ;
        RECT 12.260 0.000 13.860 446.080 ;
    END
    PORT
      LAYER met4 ;
        RECT 42.260 0.000 43.860 446.080 ;
    END
  END VGND
  PIN VPWR
    DIRECTION INOUT ;
    USE POWER ;
    PORT
      LAYER met4 ;
        RECT 6.960 0.000 8.560 446.080 ;
    END
    PORT
      LAYER met4 ;
        RECT 36.960 0.000 38.560 446.080 ;
    END
  END VPWR
  OBS
      LAYER nwell ;
        RECT 2.570 2.635 62.750 443.445 ;
      LAYER li1 ;
        RECT 2.760 2.635 62.560 443.445 ;
      LAYER met1 ;
        RECT 0.530 2.080 64.790 443.600 ;
      LAYER met2 ;
        RECT 0.160 445.520 1.190 445.800 ;
        RECT 2.030 445.520 3.490 445.800 ;
        RECT 4.330 445.520 5.790 445.800 ;
        RECT 6.630 445.520 8.090 445.800 ;
        RECT 8.930 445.520 10.390 445.800 ;
        RECT 11.230 445.520 12.690 445.800 ;
        RECT 13.530 445.520 14.990 445.800 ;
        RECT 15.830 445.520 17.290 445.800 ;
        RECT 18.130 445.520 19.590 445.800 ;
        RECT 20.430 445.520 21.890 445.800 ;
        RECT 22.730 445.520 24.190 445.800 ;
        RECT 25.030 445.520 26.490 445.800 ;
        RECT 27.330 445.520 28.790 445.800 ;
        RECT 29.630 445.520 31.090 445.800 ;
        RECT 31.930 445.520 33.390 445.800 ;
        RECT 34.230 445.520 35.690 445.800 ;
        RECT 36.530 445.520 37.990 445.800 ;
        RECT 38.830 445.520 40.290 445.800 ;
        RECT 41.130 445.520 42.590 445.800 ;
        RECT 43.430 445.520 44.890 445.800 ;
        RECT 45.730 445.520 47.190 445.800 ;
        RECT 48.030 445.520 49.490 445.800 ;
        RECT 50.330 445.520 51.790 445.800 ;
        RECT 52.630 445.520 54.090 445.800 ;
        RECT 54.930 445.520 56.390 445.800 ;
        RECT 57.230 445.520 58.690 445.800 ;
        RECT 59.530 445.520 60.990 445.800 ;
        RECT 61.830 445.520 63.290 445.800 ;
        RECT 64.130 445.520 64.770 445.800 ;
        RECT 0.160 0.560 64.770 445.520 ;
        RECT 0.160 0.270 1.190 0.560 ;
        RECT 2.030 0.270 3.490 0.560 ;
        RECT 4.330 0.270 5.790 0.560 ;
        RECT 6.630 0.270 8.090 0.560 ;
        RECT 8.930 0.270 10.390 0.560 ;
        RECT 11.230 0.270 12.690 0.560 ;
        RECT 13.530 0.270 14.990 0.560 ;
        RECT 15.830 0.270 17.290 0.560 ;
        RECT 18.130 0.270 19.590 0.560 ;
        RECT 20.430 0.270 21.890 0.560 ;
        RECT 22.730 0.270 24.190 0.560 ;
        RECT 25.030 0.270 26.490 0.560 ;
        RECT 27.330 0.270 28.790 0.560 ;
        RECT 29.630 0.270 31.090 0.560 ;
        RECT 31.930 0.270 33.390 0.560 ;
        RECT 34.230 0.270 35.690 0.560 ;
        RECT 36.530 0.270 37.990 0.560 ;
        RECT 38.830 0.270 40.290 0.560 ;
        RECT 41.130 0.270 42.590 0.560 ;
        RECT 43.430 0.270 44.890 0.560 ;
        RECT 45.730 0.270 47.190 0.560 ;
        RECT 48.030 0.270 49.490 0.560 ;
        RECT 50.330 0.270 51.790 0.560 ;
        RECT 52.630 0.270 54.090 0.560 ;
        RECT 54.930 0.270 56.390 0.560 ;
        RECT 57.230 0.270 58.690 0.560 ;
        RECT 59.530 0.270 60.990 0.560 ;
        RECT 61.830 0.270 63.290 0.560 ;
        RECT 64.130 0.270 64.770 0.560 ;
      LAYER met3 ;
        RECT 0.525 434.200 64.720 444.545 ;
        RECT 1.000 432.800 64.720 434.200 ;
        RECT 0.525 430.120 64.720 432.800 ;
        RECT 1.000 428.720 64.720 430.120 ;
        RECT 0.525 426.040 64.720 428.720 ;
        RECT 1.000 424.640 64.720 426.040 ;
        RECT 0.525 421.960 64.720 424.640 ;
        RECT 1.000 421.280 64.720 421.960 ;
        RECT 1.000 420.560 64.320 421.280 ;
        RECT 0.525 417.880 64.320 420.560 ;
        RECT 1.000 416.480 64.320 417.880 ;
        RECT 0.525 413.800 64.320 416.480 ;
        RECT 1.000 412.400 64.320 413.800 ;
        RECT 0.525 409.720 64.320 412.400 ;
        RECT 1.000 408.320 64.320 409.720 ;
        RECT 0.525 405.640 64.320 408.320 ;
        RECT 1.000 404.240 64.320 405.640 ;
        RECT 0.525 401.560 64.320 404.240 ;
        RECT 1.000 400.160 64.320 401.560 ;
        RECT 0.525 397.480 64.320 400.160 ;
        RECT 1.000 396.080 64.320 397.480 ;
        RECT 0.525 393.400 64.320 396.080 ;
        RECT 1.000 392.000 64.320 393.400 ;
        RECT 0.525 389.320 64.320 392.000 ;
        RECT 1.000 387.920 64.320 389.320 ;
        RECT 0.525 385.240 64.320 387.920 ;
        RECT 1.000 383.840 64.320 385.240 ;
        RECT 0.525 381.160 64.320 383.840 ;
        RECT 1.000 379.760 64.320 381.160 ;
        RECT 0.525 377.080 64.320 379.760 ;
        RECT 1.000 375.680 64.320 377.080 ;
        RECT 0.525 373.000 64.320 375.680 ;
        RECT 1.000 371.600 64.320 373.000 ;
        RECT 0.525 368.920 64.320 371.600 ;
        RECT 1.000 367.520 64.320 368.920 ;
        RECT 0.525 364.840 64.320 367.520 ;
        RECT 1.000 363.440 64.320 364.840 ;
        RECT 0.525 360.760 64.320 363.440 ;
        RECT 1.000 359.360 64.320 360.760 ;
        RECT 0.525 356.680 64.320 359.360 ;
        RECT 1.000 355.280 64.320 356.680 ;
        RECT 0.525 352.600 64.320 355.280 ;
        RECT 1.000 351.200 64.320 352.600 ;
        RECT 0.525 348.520 64.320 351.200 ;
        RECT 1.000 347.120 64.320 348.520 ;
        RECT 0.525 344.440 64.320 347.120 ;
        RECT 1.000 343.040 64.320 344.440 ;
        RECT 0.525 340.360 64.320 343.040 ;
        RECT 1.000 338.960 64.320 340.360 ;
        RECT 0.525 336.280 64.320 338.960 ;
        RECT 1.000 334.880 64.320 336.280 ;
        RECT 0.525 332.200 64.320 334.880 ;
        RECT 1.000 330.800 64.320 332.200 ;
        RECT 0.525 328.120 64.320 330.800 ;
        RECT 1.000 326.720 64.320 328.120 ;
        RECT 0.525 324.040 64.320 326.720 ;
        RECT 1.000 322.640 64.320 324.040 ;
        RECT 0.525 319.960 64.320 322.640 ;
        RECT 1.000 318.560 64.320 319.960 ;
        RECT 0.525 315.880 64.320 318.560 ;
        RECT 1.000 314.480 64.320 315.880 ;
        RECT 0.525 311.800 64.320 314.480 ;
        RECT 1.000 310.400 64.320 311.800 ;
        RECT 0.525 307.720 64.320 310.400 ;
        RECT 1.000 306.320 64.320 307.720 ;
        RECT 0.525 285.280 64.320 306.320 ;
        RECT 1.000 283.880 64.320 285.280 ;
        RECT 0.525 281.200 64.320 283.880 ;
        RECT 1.000 279.800 64.320 281.200 ;
        RECT 0.525 277.120 64.320 279.800 ;
        RECT 1.000 275.720 64.320 277.120 ;
        RECT 0.525 273.040 64.320 275.720 ;
        RECT 1.000 271.640 64.320 273.040 ;
        RECT 0.525 268.960 64.320 271.640 ;
        RECT 1.000 267.560 64.320 268.960 ;
        RECT 0.525 264.880 64.320 267.560 ;
        RECT 1.000 263.480 64.320 264.880 ;
        RECT 0.525 260.800 64.320 263.480 ;
        RECT 1.000 259.400 64.320 260.800 ;
        RECT 0.525 256.720 64.320 259.400 ;
        RECT 1.000 255.320 64.320 256.720 ;
        RECT 0.525 252.640 64.320 255.320 ;
        RECT 1.000 251.240 64.320 252.640 ;
        RECT 0.525 248.560 64.320 251.240 ;
        RECT 1.000 247.160 64.320 248.560 ;
        RECT 0.525 244.480 64.720 247.160 ;
        RECT 1.000 243.080 64.720 244.480 ;
        RECT 0.525 240.400 64.720 243.080 ;
        RECT 1.000 239.000 64.720 240.400 ;
        RECT 0.525 236.320 64.720 239.000 ;
        RECT 1.000 234.920 64.720 236.320 ;
        RECT 0.525 232.240 64.720 234.920 ;
        RECT 1.000 230.840 64.720 232.240 ;
        RECT 0.525 228.160 64.720 230.840 ;
        RECT 1.000 226.760 64.720 228.160 ;
        RECT 0.525 224.080 64.720 226.760 ;
        RECT 1.000 222.680 64.720 224.080 ;
        RECT 0.525 220.000 64.720 222.680 ;
        RECT 1.000 218.600 64.720 220.000 ;
        RECT 0.525 215.920 64.720 218.600 ;
        RECT 1.000 214.520 64.720 215.920 ;
        RECT 0.525 211.840 64.720 214.520 ;
        RECT 1.000 210.440 64.720 211.840 ;
        RECT 0.525 207.760 64.720 210.440 ;
        RECT 1.000 206.360 64.720 207.760 ;
        RECT 0.525 203.680 64.720 206.360 ;
        RECT 1.000 202.280 64.720 203.680 ;
        RECT 0.525 199.600 64.720 202.280 ;
        RECT 1.000 198.240 64.720 199.600 ;
        RECT 1.000 198.200 64.320 198.240 ;
        RECT 0.525 195.520 64.320 198.200 ;
        RECT 1.000 194.120 64.320 195.520 ;
        RECT 0.525 191.440 64.320 194.120 ;
        RECT 1.000 190.040 64.320 191.440 ;
        RECT 0.525 187.360 64.320 190.040 ;
        RECT 1.000 185.960 64.320 187.360 ;
        RECT 0.525 183.280 64.320 185.960 ;
        RECT 1.000 181.880 64.320 183.280 ;
        RECT 0.525 179.200 64.320 181.880 ;
        RECT 1.000 177.800 64.320 179.200 ;
        RECT 0.525 175.120 64.320 177.800 ;
        RECT 1.000 173.720 64.320 175.120 ;
        RECT 0.525 171.040 64.320 173.720 ;
        RECT 1.000 169.640 64.320 171.040 ;
        RECT 0.525 166.960 64.320 169.640 ;
        RECT 1.000 165.560 64.320 166.960 ;
        RECT 0.525 162.880 64.320 165.560 ;
        RECT 1.000 161.480 64.320 162.880 ;
        RECT 0.525 158.800 64.320 161.480 ;
        RECT 1.000 157.400 64.320 158.800 ;
        RECT 0.525 131.600 64.320 157.400 ;
        RECT 1.000 130.200 64.320 131.600 ;
        RECT 0.525 128.880 64.320 130.200 ;
        RECT 1.000 127.480 64.320 128.880 ;
        RECT 0.525 126.160 64.320 127.480 ;
        RECT 1.000 124.760 64.320 126.160 ;
        RECT 0.525 123.440 64.320 124.760 ;
        RECT 1.000 122.040 64.320 123.440 ;
        RECT 0.525 120.720 64.320 122.040 ;
        RECT 1.000 119.320 64.320 120.720 ;
        RECT 0.525 118.000 64.320 119.320 ;
        RECT 1.000 116.600 64.320 118.000 ;
        RECT 0.525 115.280 64.320 116.600 ;
        RECT 1.000 113.880 64.320 115.280 ;
        RECT 0.525 112.560 64.320 113.880 ;
        RECT 1.000 111.160 64.320 112.560 ;
        RECT 0.525 109.840 64.320 111.160 ;
        RECT 1.000 108.440 64.320 109.840 ;
        RECT 0.525 107.120 64.320 108.440 ;
        RECT 1.000 105.720 64.320 107.120 ;
        RECT 0.525 104.400 64.320 105.720 ;
        RECT 1.000 103.000 64.320 104.400 ;
        RECT 0.525 101.680 64.320 103.000 ;
        RECT 1.000 100.280 64.320 101.680 ;
        RECT 0.525 98.960 64.320 100.280 ;
        RECT 1.000 97.560 64.320 98.960 ;
        RECT 0.525 96.240 64.320 97.560 ;
        RECT 1.000 94.840 64.320 96.240 ;
        RECT 0.525 93.520 64.320 94.840 ;
        RECT 1.000 92.120 64.320 93.520 ;
        RECT 0.525 90.800 64.320 92.120 ;
        RECT 1.000 89.400 64.320 90.800 ;
        RECT 0.525 88.080 64.320 89.400 ;
        RECT 1.000 86.680 64.320 88.080 ;
        RECT 0.525 85.360 64.320 86.680 ;
        RECT 1.000 83.960 64.320 85.360 ;
        RECT 0.525 82.640 64.320 83.960 ;
        RECT 1.000 81.240 64.320 82.640 ;
        RECT 0.525 79.920 64.320 81.240 ;
        RECT 1.000 78.520 64.320 79.920 ;
        RECT 0.525 77.200 64.320 78.520 ;
        RECT 1.000 75.800 64.320 77.200 ;
        RECT 0.525 74.480 64.320 75.800 ;
        RECT 1.000 73.080 64.320 74.480 ;
        RECT 0.525 71.760 64.320 73.080 ;
        RECT 1.000 70.360 64.320 71.760 ;
        RECT 0.525 69.040 64.320 70.360 ;
        RECT 1.000 67.640 64.320 69.040 ;
        RECT 0.525 66.320 64.320 67.640 ;
        RECT 1.000 64.920 64.320 66.320 ;
        RECT 0.525 63.600 64.320 64.920 ;
        RECT 1.000 62.200 64.320 63.600 ;
        RECT 0.525 60.880 64.320 62.200 ;
        RECT 1.000 59.480 64.320 60.880 ;
        RECT 0.525 58.160 64.320 59.480 ;
        RECT 1.000 56.760 64.320 58.160 ;
        RECT 0.525 55.440 64.320 56.760 ;
        RECT 1.000 54.040 64.320 55.440 ;
        RECT 0.525 52.720 64.320 54.040 ;
        RECT 1.000 51.320 64.320 52.720 ;
        RECT 0.525 50.000 64.320 51.320 ;
        RECT 1.000 48.600 64.320 50.000 ;
        RECT 0.525 47.280 64.320 48.600 ;
        RECT 1.000 45.880 64.320 47.280 ;
        RECT 0.525 44.560 64.320 45.880 ;
        RECT 1.000 43.160 64.320 44.560 ;
        RECT 0.525 41.840 64.320 43.160 ;
        RECT 1.000 40.440 64.320 41.840 ;
        RECT 0.525 39.120 64.320 40.440 ;
        RECT 1.000 37.720 64.320 39.120 ;
        RECT 0.525 36.400 64.320 37.720 ;
        RECT 1.000 35.000 64.320 36.400 ;
        RECT 0.525 33.680 64.320 35.000 ;
        RECT 1.000 32.280 64.320 33.680 ;
        RECT 0.525 30.960 64.320 32.280 ;
        RECT 1.000 29.560 64.320 30.960 ;
        RECT 0.525 28.240 64.320 29.560 ;
        RECT 1.000 26.840 64.320 28.240 ;
        RECT 0.525 25.520 64.320 26.840 ;
        RECT 1.000 24.120 64.320 25.520 ;
        RECT 0.525 22.800 64.720 24.120 ;
        RECT 1.000 21.400 64.720 22.800 ;
        RECT 0.525 20.080 64.720 21.400 ;
        RECT 1.000 18.680 64.720 20.080 ;
        RECT 0.525 17.360 64.720 18.680 ;
        RECT 1.000 15.960 64.720 17.360 ;
        RECT 0.525 2.555 64.720 15.960 ;
      LAYER met4 ;
        RECT 0.310 4.255 6.560 444.545 ;
        RECT 8.960 4.255 11.860 444.545 ;
        RECT 14.260 4.255 36.560 444.545 ;
        RECT 38.960 4.255 41.860 444.545 ;
        RECT 44.260 4.255 64.105 444.545 ;
  END
END W_TT_IF2
END LIBRARY

